VERSION 5.8 ;
BUSBITCHARS "[]" ;
DIVIDERCHAR "/" ;
UNITS
    DATABASE MICRONS 1000 ;
END UNITS

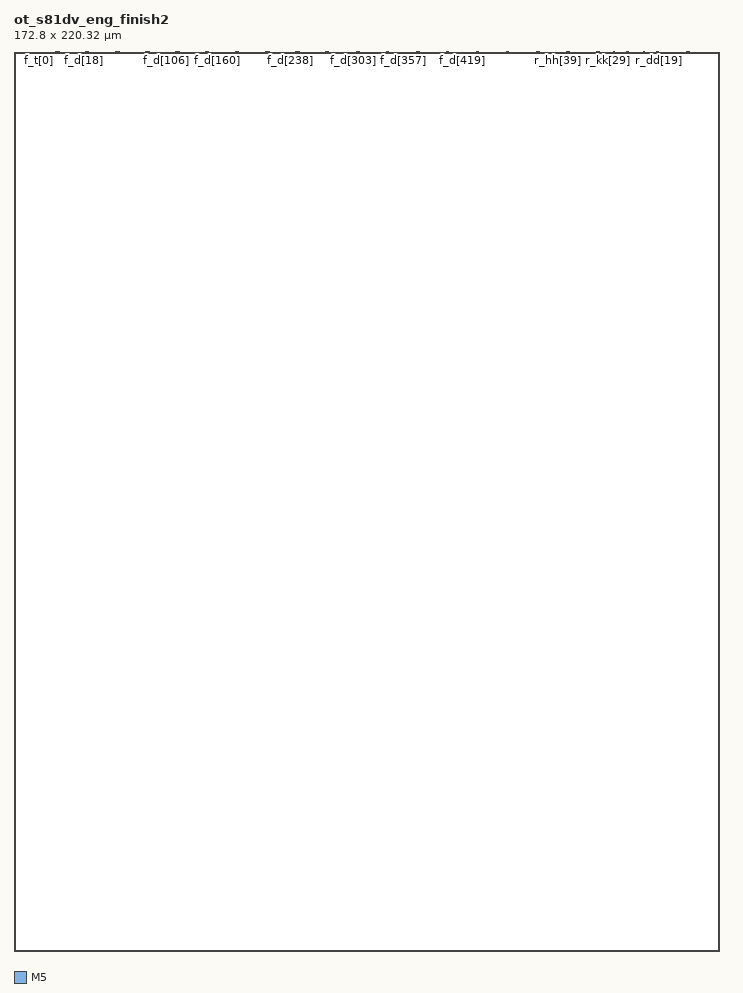
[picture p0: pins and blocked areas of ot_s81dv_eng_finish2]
MACRO ot_s81dv_eng_finish2
  FOREIGN ot_s81dv_eng_finish2 0 0 ;
  CLASS BLOCK ;
  SIZE 172.8 BY 220.32 ;
  PIN go[0]
    DIRECTION INPUT ;
    USE SIGNAL ;
    PORT
      LAYER M5 ;
        RECT 4.3200 220.2360 4.3440 220.3200 ;
    END
  END go[0]
  PIN go[1]
    DIRECTION INPUT ;
    USE SIGNAL ;
    PORT
      LAYER M5 ;
        RECT 4.5600 220.2360 4.5840 220.3200 ;
    END
  END go[1]
  PIN f_v[0]
    DIRECTION INPUT ;
    USE SIGNAL ;
    PORT
      LAYER M5 ;
        RECT 4.8000 220.2360 4.8240 220.3200 ;
    END
  END f_v[0]
  PIN f_v[1]
    DIRECTION INPUT ;
    USE SIGNAL ;
    PORT
      LAYER M5 ;
        RECT 4.9920 220.2360 5.0160 220.3200 ;
    END
  END f_v[1]
  PIN f_v[2]
    DIRECTION INPUT ;
    USE SIGNAL ;
    PORT
      LAYER M5 ;
        RECT 5.2320 220.2360 5.2560 220.3200 ;
    END
  END f_v[2]
  PIN f_v[3]
    DIRECTION INPUT ;
    USE SIGNAL ;
    PORT
      LAYER M5 ;
        RECT 5.4720 220.2360 5.4960 220.3200 ;
    END
  END f_v[3]
  PIN f_v[4]
    DIRECTION INPUT ;
    USE SIGNAL ;
    PORT
      LAYER M5 ;
        RECT 5.7120 220.2360 5.7360 220.3200 ;
    END
  END f_v[4]
  PIN f_v[5]
    DIRECTION INPUT ;
    USE SIGNAL ;
    PORT
      LAYER M5 ;
        RECT 5.9040 220.2360 5.9280 220.3200 ;
    END
  END f_v[5]
  PIN f_t[0]
    DIRECTION INPUT ;
    USE SIGNAL ;
    PORT
      LAYER M5 ;
        RECT 6.1440 220.2360 6.1680 220.3200 ;
    END
  END f_t[0]
  PIN f_t[1]
    DIRECTION INPUT ;
    USE SIGNAL ;
    PORT
      LAYER M5 ;
        RECT 6.3840 220.2360 6.4080 220.3200 ;
    END
  END f_t[1]
  PIN f_t[2]
    DIRECTION INPUT ;
    USE SIGNAL ;
    PORT
      LAYER M5 ;
        RECT 6.6240 220.2360 6.6480 220.3200 ;
    END
  END f_t[2]
  PIN f_t[3]
    DIRECTION INPUT ;
    USE SIGNAL ;
    PORT
      LAYER M5 ;
        RECT 6.8640 220.2360 6.8880 220.3200 ;
    END
  END f_t[3]
  PIN f_t[4]
    DIRECTION INPUT ;
    USE SIGNAL ;
    PORT
      LAYER M5 ;
        RECT 7.0560 220.2360 7.0800 220.3200 ;
    END
  END f_t[4]
  PIN f_t[5]
    DIRECTION INPUT ;
    USE SIGNAL ;
    PORT
      LAYER M5 ;
        RECT 7.2960 220.2360 7.3200 220.3200 ;
    END
  END f_t[5]
  PIN f_base[0]
    DIRECTION INPUT ;
    USE SIGNAL ;
    PORT
      LAYER M5 ;
        RECT 7.5360 220.2360 7.5600 220.3200 ;
    END
  END f_base[0]
  PIN f_base[1]
    DIRECTION INPUT ;
    USE SIGNAL ;
    PORT
      LAYER M5 ;
        RECT 7.7760 220.2360 7.8000 220.3200 ;
    END
  END f_base[1]
  PIN f_base[2]
    DIRECTION INPUT ;
    USE SIGNAL ;
    PORT
      LAYER M5 ;
        RECT 8.0160 220.2360 8.0400 220.3200 ;
    END
  END f_base[2]
  PIN f_base[3]
    DIRECTION INPUT ;
    USE SIGNAL ;
    PORT
      LAYER M5 ;
        RECT 8.2080 220.2360 8.2320 220.3200 ;
    END
  END f_base[3]
  PIN f_base[4]
    DIRECTION INPUT ;
    USE SIGNAL ;
    PORT
      LAYER M5 ;
        RECT 8.4480 220.2360 8.4720 220.3200 ;
    END
  END f_base[4]
  PIN f_base[5]
    DIRECTION INPUT ;
    USE SIGNAL ;
    PORT
      LAYER M5 ;
        RECT 8.6880 220.2360 8.7120 220.3200 ;
    END
  END f_base[5]
  PIN f_base[6]
    DIRECTION INPUT ;
    USE SIGNAL ;
    PORT
      LAYER M5 ;
        RECT 8.9280 220.2360 8.9520 220.3200 ;
    END
  END f_base[6]
  PIN f_base[7]
    DIRECTION INPUT ;
    USE SIGNAL ;
    PORT
      LAYER M5 ;
        RECT 9.1200 220.2360 9.1440 220.3200 ;
    END
  END f_base[7]
  PIN f_base[8]
    DIRECTION INPUT ;
    USE SIGNAL ;
    PORT
      LAYER M5 ;
        RECT 9.3600 220.2360 9.3840 220.3200 ;
    END
  END f_base[8]
  PIN f_base[9]
    DIRECTION INPUT ;
    USE SIGNAL ;
    PORT
      LAYER M5 ;
        RECT 9.6000 220.2360 9.6240 220.3200 ;
    END
  END f_base[9]
  PIN f_base[10]
    DIRECTION INPUT ;
    USE SIGNAL ;
    PORT
      LAYER M5 ;
        RECT 9.8400 220.2360 9.8640 220.3200 ;
    END
  END f_base[10]
  PIN f_base[11]
    DIRECTION INPUT ;
    USE SIGNAL ;
    PORT
      LAYER M5 ;
        RECT 10.0800 220.2360 10.1040 220.3200 ;
    END
  END f_base[11]
  PIN f_base[12]
    DIRECTION INPUT ;
    USE SIGNAL ;
    PORT
      LAYER M5 ;
        RECT 10.2720 220.2360 10.2960 220.3200 ;
    END
  END f_base[12]
  PIN f_base[13]
    DIRECTION INPUT ;
    USE SIGNAL ;
    PORT
      LAYER M5 ;
        RECT 10.5120 220.2360 10.5360 220.3200 ;
    END
  END f_base[13]
  PIN f_base[14]
    DIRECTION INPUT ;
    USE SIGNAL ;
    PORT
      LAYER M5 ;
        RECT 10.7520 220.2360 10.7760 220.3200 ;
    END
  END f_base[14]
  PIN f_base[15]
    DIRECTION INPUT ;
    USE SIGNAL ;
    PORT
      LAYER M5 ;
        RECT 10.9920 220.2360 11.0160 220.3200 ;
    END
  END f_base[15]
  PIN f_base[16]
    DIRECTION INPUT ;
    USE SIGNAL ;
    PORT
      LAYER M5 ;
        RECT 11.1840 220.2360 11.2080 220.3200 ;
    END
  END f_base[16]
  PIN f_base[17]
    DIRECTION INPUT ;
    USE SIGNAL ;
    PORT
      LAYER M5 ;
        RECT 11.4240 220.2360 11.4480 220.3200 ;
    END
  END f_base[17]
  PIN f_base[18]
    DIRECTION INPUT ;
    USE SIGNAL ;
    PORT
      LAYER M5 ;
        RECT 11.6640 220.2360 11.6880 220.3200 ;
    END
  END f_base[18]
  PIN f_base[19]
    DIRECTION INPUT ;
    USE SIGNAL ;
    PORT
      LAYER M5 ;
        RECT 11.9040 220.2360 11.9280 220.3200 ;
    END
  END f_base[19]
  PIN f_base[20]
    DIRECTION INPUT ;
    USE SIGNAL ;
    PORT
      LAYER M5 ;
        RECT 12.1440 220.2360 12.1680 220.3200 ;
    END
  END f_base[20]
  PIN f_base[21]
    DIRECTION INPUT ;
    USE SIGNAL ;
    PORT
      LAYER M5 ;
        RECT 12.3360 220.2360 12.3600 220.3200 ;
    END
  END f_base[21]
  PIN f_base[22]
    DIRECTION INPUT ;
    USE SIGNAL ;
    PORT
      LAYER M5 ;
        RECT 12.5760 220.2360 12.6000 220.3200 ;
    END
  END f_base[22]
  PIN f_base[23]
    DIRECTION INPUT ;
    USE SIGNAL ;
    PORT
      LAYER M5 ;
        RECT 12.8160 220.2360 12.8400 220.3200 ;
    END
  END f_base[23]
  PIN f_d[0]
    DIRECTION INPUT ;
    USE SIGNAL ;
    PORT
      LAYER M5 ;
        RECT 13.0560 220.2360 13.0800 220.3200 ;
    END
  END f_d[0]
  PIN f_d[1]
    DIRECTION INPUT ;
    USE SIGNAL ;
    PORT
      LAYER M5 ;
        RECT 13.2480 220.2360 13.2720 220.3200 ;
    END
  END f_d[1]
  PIN f_d[2]
    DIRECTION INPUT ;
    USE SIGNAL ;
    PORT
      LAYER M5 ;
        RECT 13.4880 220.2360 13.5120 220.3200 ;
    END
  END f_d[2]
  PIN f_d[3]
    DIRECTION INPUT ;
    USE SIGNAL ;
    PORT
      LAYER M5 ;
        RECT 13.7280 220.2360 13.7520 220.3200 ;
    END
  END f_d[3]
  PIN f_d[4]
    DIRECTION INPUT ;
    USE SIGNAL ;
    PORT
      LAYER M5 ;
        RECT 13.9680 220.2360 13.9920 220.3200 ;
    END
  END f_d[4]
  PIN f_d[5]
    DIRECTION INPUT ;
    USE SIGNAL ;
    PORT
      LAYER M5 ;
        RECT 14.2080 220.2360 14.2320 220.3200 ;
    END
  END f_d[5]
  PIN f_d[6]
    DIRECTION INPUT ;
    USE SIGNAL ;
    PORT
      LAYER M5 ;
        RECT 14.4000 220.2360 14.4240 220.3200 ;
    END
  END f_d[6]
  PIN f_d[7]
    DIRECTION INPUT ;
    USE SIGNAL ;
    PORT
      LAYER M5 ;
        RECT 14.6400 220.2360 14.6640 220.3200 ;
    END
  END f_d[7]
  PIN f_d[8]
    DIRECTION INPUT ;
    USE SIGNAL ;
    PORT
      LAYER M5 ;
        RECT 14.8800 220.2360 14.9040 220.3200 ;
    END
  END f_d[8]
  PIN f_d[9]
    DIRECTION INPUT ;
    USE SIGNAL ;
    PORT
      LAYER M5 ;
        RECT 15.1200 220.2360 15.1440 220.3200 ;
    END
  END f_d[9]
  PIN f_d[10]
    DIRECTION INPUT ;
    USE SIGNAL ;
    PORT
      LAYER M5 ;
        RECT 15.3600 220.2360 15.3840 220.3200 ;
    END
  END f_d[10]
  PIN f_d[11]
    DIRECTION INPUT ;
    USE SIGNAL ;
    PORT
      LAYER M5 ;
        RECT 15.5520 220.2360 15.5760 220.3200 ;
    END
  END f_d[11]
  PIN f_d[12]
    DIRECTION INPUT ;
    USE SIGNAL ;
    PORT
      LAYER M5 ;
        RECT 15.7920 220.2360 15.8160 220.3200 ;
    END
  END f_d[12]
  PIN f_d[13]
    DIRECTION INPUT ;
    USE SIGNAL ;
    PORT
      LAYER M5 ;
        RECT 16.0320 220.2360 16.0560 220.3200 ;
    END
  END f_d[13]
  PIN f_d[14]
    DIRECTION INPUT ;
    USE SIGNAL ;
    PORT
      LAYER M5 ;
        RECT 16.2720 220.2360 16.2960 220.3200 ;
    END
  END f_d[14]
  PIN f_d[15]
    DIRECTION INPUT ;
    USE SIGNAL ;
    PORT
      LAYER M5 ;
        RECT 16.4640 220.2360 16.4880 220.3200 ;
    END
  END f_d[15]
  PIN f_d[16]
    DIRECTION INPUT ;
    USE SIGNAL ;
    PORT
      LAYER M5 ;
        RECT 16.7040 220.2360 16.7280 220.3200 ;
    END
  END f_d[16]
  PIN f_d[17]
    DIRECTION INPUT ;
    USE SIGNAL ;
    PORT
      LAYER M5 ;
        RECT 16.9440 220.2360 16.9680 220.3200 ;
    END
  END f_d[17]
  PIN f_d[18]
    DIRECTION INPUT ;
    USE SIGNAL ;
    PORT
      LAYER M5 ;
        RECT 17.1840 220.2360 17.2080 220.3200 ;
    END
  END f_d[18]
  PIN f_d[19]
    DIRECTION INPUT ;
    USE SIGNAL ;
    PORT
      LAYER M5 ;
        RECT 17.4240 220.2360 17.4480 220.3200 ;
    END
  END f_d[19]
  PIN f_d[20]
    DIRECTION INPUT ;
    USE SIGNAL ;
    PORT
      LAYER M5 ;
        RECT 17.6160 220.2360 17.6400 220.3200 ;
    END
  END f_d[20]
  PIN f_d[21]
    DIRECTION INPUT ;
    USE SIGNAL ;
    PORT
      LAYER M5 ;
        RECT 17.8560 220.2360 17.8800 220.3200 ;
    END
  END f_d[21]
  PIN f_d[22]
    DIRECTION INPUT ;
    USE SIGNAL ;
    PORT
      LAYER M5 ;
        RECT 18.0960 220.2360 18.1200 220.3200 ;
    END
  END f_d[22]
  PIN f_d[23]
    DIRECTION INPUT ;
    USE SIGNAL ;
    PORT
      LAYER M5 ;
        RECT 18.3360 220.2360 18.3600 220.3200 ;
    END
  END f_d[23]
  PIN f_d[24]
    DIRECTION INPUT ;
    USE SIGNAL ;
    PORT
      LAYER M5 ;
        RECT 18.5280 220.2360 18.5520 220.3200 ;
    END
  END f_d[24]
  PIN f_d[25]
    DIRECTION INPUT ;
    USE SIGNAL ;
    PORT
      LAYER M5 ;
        RECT 18.7680 220.2360 18.7920 220.3200 ;
    END
  END f_d[25]
  PIN f_d[26]
    DIRECTION INPUT ;
    USE SIGNAL ;
    PORT
      LAYER M5 ;
        RECT 19.0080 220.2360 19.0320 220.3200 ;
    END
  END f_d[26]
  PIN f_d[27]
    DIRECTION INPUT ;
    USE SIGNAL ;
    PORT
      LAYER M5 ;
        RECT 19.2480 220.2360 19.2720 220.3200 ;
    END
  END f_d[27]
  PIN f_d[28]
    DIRECTION INPUT ;
    USE SIGNAL ;
    PORT
      LAYER M5 ;
        RECT 19.4880 220.2360 19.5120 220.3200 ;
    END
  END f_d[28]
  PIN f_d[29]
    DIRECTION INPUT ;
    USE SIGNAL ;
    PORT
      LAYER M5 ;
        RECT 19.6800 220.2360 19.7040 220.3200 ;
    END
  END f_d[29]
  PIN f_d[30]
    DIRECTION INPUT ;
    USE SIGNAL ;
    PORT
      LAYER M5 ;
        RECT 19.9200 220.2360 19.9440 220.3200 ;
    END
  END f_d[30]
  PIN f_d[31]
    DIRECTION INPUT ;
    USE SIGNAL ;
    PORT
      LAYER M5 ;
        RECT 20.1600 220.2360 20.1840 220.3200 ;
    END
  END f_d[31]
  PIN f_d[32]
    DIRECTION INPUT ;
    USE SIGNAL ;
    PORT
      LAYER M5 ;
        RECT 20.4000 220.2360 20.4240 220.3200 ;
    END
  END f_d[32]
  PIN f_d[33]
    DIRECTION INPUT ;
    USE SIGNAL ;
    PORT
      LAYER M5 ;
        RECT 20.6400 220.2360 20.6640 220.3200 ;
    END
  END f_d[33]
  PIN f_d[34]
    DIRECTION INPUT ;
    USE SIGNAL ;
    PORT
      LAYER M5 ;
        RECT 20.8320 220.2360 20.8560 220.3200 ;
    END
  END f_d[34]
  PIN f_d[35]
    DIRECTION INPUT ;
    USE SIGNAL ;
    PORT
      LAYER M5 ;
        RECT 21.0720 220.2360 21.0960 220.3200 ;
    END
  END f_d[35]
  PIN f_d[36]
    DIRECTION INPUT ;
    USE SIGNAL ;
    PORT
      LAYER M5 ;
        RECT 21.3120 220.2360 21.3360 220.3200 ;
    END
  END f_d[36]
  PIN f_d[37]
    DIRECTION INPUT ;
    USE SIGNAL ;
    PORT
      LAYER M5 ;
        RECT 21.5520 220.2360 21.5760 220.3200 ;
    END
  END f_d[37]
  PIN f_d[38]
    DIRECTION INPUT ;
    USE SIGNAL ;
    PORT
      LAYER M5 ;
        RECT 21.7440 220.2360 21.7680 220.3200 ;
    END
  END f_d[38]
  PIN f_d[39]
    DIRECTION INPUT ;
    USE SIGNAL ;
    PORT
      LAYER M5 ;
        RECT 21.9840 220.2360 22.0080 220.3200 ;
    END
  END f_d[39]
  PIN f_d[40]
    DIRECTION INPUT ;
    USE SIGNAL ;
    PORT
      LAYER M5 ;
        RECT 22.2240 220.2360 22.2480 220.3200 ;
    END
  END f_d[40]
  PIN f_d[41]
    DIRECTION INPUT ;
    USE SIGNAL ;
    PORT
      LAYER M5 ;
        RECT 22.4640 220.2360 22.4880 220.3200 ;
    END
  END f_d[41]
  PIN f_d[42]
    DIRECTION INPUT ;
    USE SIGNAL ;
    PORT
      LAYER M5 ;
        RECT 22.7040 220.2360 22.7280 220.3200 ;
    END
  END f_d[42]
  PIN f_d[43]
    DIRECTION INPUT ;
    USE SIGNAL ;
    PORT
      LAYER M5 ;
        RECT 22.8960 220.2360 22.9200 220.3200 ;
    END
  END f_d[43]
  PIN f_d[44]
    DIRECTION INPUT ;
    USE SIGNAL ;
    PORT
      LAYER M5 ;
        RECT 23.1360 220.2360 23.1600 220.3200 ;
    END
  END f_d[44]
  PIN f_d[45]
    DIRECTION INPUT ;
    USE SIGNAL ;
    PORT
      LAYER M5 ;
        RECT 23.3760 220.2360 23.4000 220.3200 ;
    END
  END f_d[45]
  PIN f_d[46]
    DIRECTION INPUT ;
    USE SIGNAL ;
    PORT
      LAYER M5 ;
        RECT 23.6160 220.2360 23.6400 220.3200 ;
    END
  END f_d[46]
  PIN f_d[47]
    DIRECTION INPUT ;
    USE SIGNAL ;
    PORT
      LAYER M5 ;
        RECT 23.8080 220.2360 23.8320 220.3200 ;
    END
  END f_d[47]
  PIN f_d[48]
    DIRECTION INPUT ;
    USE SIGNAL ;
    PORT
      LAYER M5 ;
        RECT 24.0480 220.2360 24.0720 220.3200 ;
    END
  END f_d[48]
  PIN f_d[49]
    DIRECTION INPUT ;
    USE SIGNAL ;
    PORT
      LAYER M5 ;
        RECT 24.2880 220.2360 24.3120 220.3200 ;
    END
  END f_d[49]
  PIN f_d[50]
    DIRECTION INPUT ;
    USE SIGNAL ;
    PORT
      LAYER M5 ;
        RECT 24.5280 220.2360 24.5520 220.3200 ;
    END
  END f_d[50]
  PIN f_d[51]
    DIRECTION INPUT ;
    USE SIGNAL ;
    PORT
      LAYER M5 ;
        RECT 24.7680 220.2360 24.7920 220.3200 ;
    END
  END f_d[51]
  PIN f_d[52]
    DIRECTION INPUT ;
    USE SIGNAL ;
    PORT
      LAYER M5 ;
        RECT 24.9600 220.2360 24.9840 220.3200 ;
    END
  END f_d[52]
  PIN f_d[53]
    DIRECTION INPUT ;
    USE SIGNAL ;
    PORT
      LAYER M5 ;
        RECT 25.2000 220.2360 25.2240 220.3200 ;
    END
  END f_d[53]
  PIN f_d[54]
    DIRECTION INPUT ;
    USE SIGNAL ;
    PORT
      LAYER M5 ;
        RECT 25.4400 220.2360 25.4640 220.3200 ;
    END
  END f_d[54]
  PIN f_d[55]
    DIRECTION INPUT ;
    USE SIGNAL ;
    PORT
      LAYER M5 ;
        RECT 25.6800 220.2360 25.7040 220.3200 ;
    END
  END f_d[55]
  PIN f_d[56]
    DIRECTION INPUT ;
    USE SIGNAL ;
    PORT
      LAYER M5 ;
        RECT 25.8720 220.2360 25.8960 220.3200 ;
    END
  END f_d[56]
  PIN f_d[57]
    DIRECTION INPUT ;
    USE SIGNAL ;
    PORT
      LAYER M5 ;
        RECT 26.1120 220.2360 26.1360 220.3200 ;
    END
  END f_d[57]
  PIN f_d[58]
    DIRECTION INPUT ;
    USE SIGNAL ;
    PORT
      LAYER M5 ;
        RECT 26.3520 220.2360 26.3760 220.3200 ;
    END
  END f_d[58]
  PIN f_d[59]
    DIRECTION INPUT ;
    USE SIGNAL ;
    PORT
      LAYER M5 ;
        RECT 26.5920 220.2360 26.6160 220.3200 ;
    END
  END f_d[59]
  PIN f_d[60]
    DIRECTION INPUT ;
    USE SIGNAL ;
    PORT
      LAYER M5 ;
        RECT 26.8320 220.2360 26.8560 220.3200 ;
    END
  END f_d[60]
  PIN f_d[61]
    DIRECTION INPUT ;
    USE SIGNAL ;
    PORT
      LAYER M5 ;
        RECT 27.0240 220.2360 27.0480 220.3200 ;
    END
  END f_d[61]
  PIN f_d[62]
    DIRECTION INPUT ;
    USE SIGNAL ;
    PORT
      LAYER M5 ;
        RECT 27.2640 220.2360 27.2880 220.3200 ;
    END
  END f_d[62]
  PIN f_d[63]
    DIRECTION INPUT ;
    USE SIGNAL ;
    PORT
      LAYER M5 ;
        RECT 27.5040 220.2360 27.5280 220.3200 ;
    END
  END f_d[63]
  PIN f_d[64]
    DIRECTION INPUT ;
    USE SIGNAL ;
    PORT
      LAYER M5 ;
        RECT 27.7440 220.2360 27.7680 220.3200 ;
    END
  END f_d[64]
  PIN f_d[65]
    DIRECTION INPUT ;
    USE SIGNAL ;
    PORT
      LAYER M5 ;
        RECT 27.9840 220.2360 28.0080 220.3200 ;
    END
  END f_d[65]
  PIN f_d[66]
    DIRECTION INPUT ;
    USE SIGNAL ;
    PORT
      LAYER M5 ;
        RECT 28.1760 220.2360 28.2000 220.3200 ;
    END
  END f_d[66]
  PIN f_d[67]
    DIRECTION INPUT ;
    USE SIGNAL ;
    PORT
      LAYER M5 ;
        RECT 28.4160 220.2360 28.4400 220.3200 ;
    END
  END f_d[67]
  PIN f_d[68]
    DIRECTION INPUT ;
    USE SIGNAL ;
    PORT
      LAYER M5 ;
        RECT 28.6560 220.2360 28.6800 220.3200 ;
    END
  END f_d[68]
  PIN f_d[69]
    DIRECTION INPUT ;
    USE SIGNAL ;
    PORT
      LAYER M5 ;
        RECT 28.8960 220.2360 28.9200 220.3200 ;
    END
  END f_d[69]
  PIN f_d[70]
    DIRECTION INPUT ;
    USE SIGNAL ;
    PORT
      LAYER M5 ;
        RECT 29.0880 220.2360 29.1120 220.3200 ;
    END
  END f_d[70]
  PIN f_d[71]
    DIRECTION INPUT ;
    USE SIGNAL ;
    PORT
      LAYER M5 ;
        RECT 29.3280 220.2360 29.3520 220.3200 ;
    END
  END f_d[71]
  PIN f_d[72]
    DIRECTION INPUT ;
    USE SIGNAL ;
    PORT
      LAYER M5 ;
        RECT 29.5680 220.2360 29.5920 220.3200 ;
    END
  END f_d[72]
  PIN f_d[73]
    DIRECTION INPUT ;
    USE SIGNAL ;
    PORT
      LAYER M5 ;
        RECT 29.8080 220.2360 29.8320 220.3200 ;
    END
  END f_d[73]
  PIN f_d[74]
    DIRECTION INPUT ;
    USE SIGNAL ;
    PORT
      LAYER M5 ;
        RECT 30.0480 220.2360 30.0720 220.3200 ;
    END
  END f_d[74]
  PIN f_d[75]
    DIRECTION INPUT ;
    USE SIGNAL ;
    PORT
      LAYER M5 ;
        RECT 30.2400 220.2360 30.2640 220.3200 ;
    END
  END f_d[75]
  PIN f_d[76]
    DIRECTION INPUT ;
    USE SIGNAL ;
    PORT
      LAYER M5 ;
        RECT 30.4800 220.2360 30.5040 220.3200 ;
    END
  END f_d[76]
  PIN f_d[77]
    DIRECTION INPUT ;
    USE SIGNAL ;
    PORT
      LAYER M5 ;
        RECT 30.7200 220.2360 30.7440 220.3200 ;
    END
  END f_d[77]
  PIN f_d[78]
    DIRECTION INPUT ;
    USE SIGNAL ;
    PORT
      LAYER M5 ;
        RECT 30.9600 220.2360 30.9840 220.3200 ;
    END
  END f_d[78]
  PIN f_d[79]
    DIRECTION INPUT ;
    USE SIGNAL ;
    PORT
      LAYER M5 ;
        RECT 31.1520 220.2360 31.1760 220.3200 ;
    END
  END f_d[79]
  PIN f_d[80]
    DIRECTION INPUT ;
    USE SIGNAL ;
    PORT
      LAYER M5 ;
        RECT 31.3920 220.2360 31.4160 220.3200 ;
    END
  END f_d[80]
  PIN f_d[81]
    DIRECTION INPUT ;
    USE SIGNAL ;
    PORT
      LAYER M5 ;
        RECT 31.6320 220.2360 31.6560 220.3200 ;
    END
  END f_d[81]
  PIN f_d[82]
    DIRECTION INPUT ;
    USE SIGNAL ;
    PORT
      LAYER M5 ;
        RECT 31.8720 220.2360 31.8960 220.3200 ;
    END
  END f_d[82]
  PIN f_d[83]
    DIRECTION INPUT ;
    USE SIGNAL ;
    PORT
      LAYER M5 ;
        RECT 32.1120 220.2360 32.1360 220.3200 ;
    END
  END f_d[83]
  PIN f_d[84]
    DIRECTION INPUT ;
    USE SIGNAL ;
    PORT
      LAYER M5 ;
        RECT 32.3040 220.2360 32.3280 220.3200 ;
    END
  END f_d[84]
  PIN f_d[85]
    DIRECTION INPUT ;
    USE SIGNAL ;
    PORT
      LAYER M5 ;
        RECT 32.5440 220.2360 32.5680 220.3200 ;
    END
  END f_d[85]
  PIN f_d[86]
    DIRECTION INPUT ;
    USE SIGNAL ;
    PORT
      LAYER M5 ;
        RECT 32.7840 220.2360 32.8080 220.3200 ;
    END
  END f_d[86]
  PIN f_d[87]
    DIRECTION INPUT ;
    USE SIGNAL ;
    PORT
      LAYER M5 ;
        RECT 33.0240 220.2360 33.0480 220.3200 ;
    END
  END f_d[87]
  PIN f_d[88]
    DIRECTION INPUT ;
    USE SIGNAL ;
    PORT
      LAYER M5 ;
        RECT 33.2640 220.2360 33.2880 220.3200 ;
    END
  END f_d[88]
  PIN f_d[89]
    DIRECTION INPUT ;
    USE SIGNAL ;
    PORT
      LAYER M5 ;
        RECT 33.4560 220.2360 33.4800 220.3200 ;
    END
  END f_d[89]
  PIN f_d[90]
    DIRECTION INPUT ;
    USE SIGNAL ;
    PORT
      LAYER M5 ;
        RECT 33.6960 220.2360 33.7200 220.3200 ;
    END
  END f_d[90]
  PIN f_d[91]
    DIRECTION INPUT ;
    USE SIGNAL ;
    PORT
      LAYER M5 ;
        RECT 33.9360 220.2360 33.9600 220.3200 ;
    END
  END f_d[91]
  PIN f_d[92]
    DIRECTION INPUT ;
    USE SIGNAL ;
    PORT
      LAYER M5 ;
        RECT 34.1760 220.2360 34.2000 220.3200 ;
    END
  END f_d[92]
  PIN f_d[93]
    DIRECTION INPUT ;
    USE SIGNAL ;
    PORT
      LAYER M5 ;
        RECT 34.3680 220.2360 34.3920 220.3200 ;
    END
  END f_d[93]
  PIN f_d[94]
    DIRECTION INPUT ;
    USE SIGNAL ;
    PORT
      LAYER M5 ;
        RECT 34.6080 220.2360 34.6320 220.3200 ;
    END
  END f_d[94]
  PIN f_d[95]
    DIRECTION INPUT ;
    USE SIGNAL ;
    PORT
      LAYER M5 ;
        RECT 34.8480 220.2360 34.8720 220.3200 ;
    END
  END f_d[95]
  PIN f_d[96]
    DIRECTION INPUT ;
    USE SIGNAL ;
    PORT
      LAYER M5 ;
        RECT 35.0880 220.2360 35.1120 220.3200 ;
    END
  END f_d[96]
  PIN f_d[97]
    DIRECTION INPUT ;
    USE SIGNAL ;
    PORT
      LAYER M5 ;
        RECT 35.3280 220.2360 35.3520 220.3200 ;
    END
  END f_d[97]
  PIN f_d[98]
    DIRECTION INPUT ;
    USE SIGNAL ;
    PORT
      LAYER M5 ;
        RECT 35.5200 220.2360 35.5440 220.3200 ;
    END
  END f_d[98]
  PIN f_d[99]
    DIRECTION INPUT ;
    USE SIGNAL ;
    PORT
      LAYER M5 ;
        RECT 35.7600 220.2360 35.7840 220.3200 ;
    END
  END f_d[99]
  PIN f_d[100]
    DIRECTION INPUT ;
    USE SIGNAL ;
    PORT
      LAYER M5 ;
        RECT 36.0000 220.2360 36.0240 220.3200 ;
    END
  END f_d[100]
  PIN f_d[101]
    DIRECTION INPUT ;
    USE SIGNAL ;
    PORT
      LAYER M5 ;
        RECT 36.2400 220.2360 36.2640 220.3200 ;
    END
  END f_d[101]
  PIN f_d[102]
    DIRECTION INPUT ;
    USE SIGNAL ;
    PORT
      LAYER M5 ;
        RECT 36.4320 220.2360 36.4560 220.3200 ;
    END
  END f_d[102]
  PIN f_d[103]
    DIRECTION INPUT ;
    USE SIGNAL ;
    PORT
      LAYER M5 ;
        RECT 36.6720 220.2360 36.6960 220.3200 ;
    END
  END f_d[103]
  PIN f_d[104]
    DIRECTION INPUT ;
    USE SIGNAL ;
    PORT
      LAYER M5 ;
        RECT 36.9120 220.2360 36.9360 220.3200 ;
    END
  END f_d[104]
  PIN f_d[105]
    DIRECTION INPUT ;
    USE SIGNAL ;
    PORT
      LAYER M5 ;
        RECT 37.1520 220.2360 37.1760 220.3200 ;
    END
  END f_d[105]
  PIN f_d[106]
    DIRECTION INPUT ;
    USE SIGNAL ;
    PORT
      LAYER M5 ;
        RECT 37.3920 220.2360 37.4160 220.3200 ;
    END
  END f_d[106]
  PIN f_d[107]
    DIRECTION INPUT ;
    USE SIGNAL ;
    PORT
      LAYER M5 ;
        RECT 37.5840 220.2360 37.6080 220.3200 ;
    END
  END f_d[107]
  PIN f_d[108]
    DIRECTION INPUT ;
    USE SIGNAL ;
    PORT
      LAYER M5 ;
        RECT 37.8240 220.2360 37.8480 220.3200 ;
    END
  END f_d[108]
  PIN f_d[109]
    DIRECTION INPUT ;
    USE SIGNAL ;
    PORT
      LAYER M5 ;
        RECT 38.0640 220.2360 38.0880 220.3200 ;
    END
  END f_d[109]
  PIN f_d[110]
    DIRECTION INPUT ;
    USE SIGNAL ;
    PORT
      LAYER M5 ;
        RECT 38.3040 220.2360 38.3280 220.3200 ;
    END
  END f_d[110]
  PIN f_d[111]
    DIRECTION INPUT ;
    USE SIGNAL ;
    PORT
      LAYER M5 ;
        RECT 38.4960 220.2360 38.5200 220.3200 ;
    END
  END f_d[111]
  PIN f_d[112]
    DIRECTION INPUT ;
    USE SIGNAL ;
    PORT
      LAYER M5 ;
        RECT 38.7360 220.2360 38.7600 220.3200 ;
    END
  END f_d[112]
  PIN f_d[113]
    DIRECTION INPUT ;
    USE SIGNAL ;
    PORT
      LAYER M5 ;
        RECT 38.9760 220.2360 39.0000 220.3200 ;
    END
  END f_d[113]
  PIN f_d[114]
    DIRECTION INPUT ;
    USE SIGNAL ;
    PORT
      LAYER M5 ;
        RECT 39.2160 220.2360 39.2400 220.3200 ;
    END
  END f_d[114]
  PIN f_d[115]
    DIRECTION INPUT ;
    USE SIGNAL ;
    PORT
      LAYER M5 ;
        RECT 39.4560 220.2360 39.4800 220.3200 ;
    END
  END f_d[115]
  PIN f_d[116]
    DIRECTION INPUT ;
    USE SIGNAL ;
    PORT
      LAYER M5 ;
        RECT 39.6480 220.2360 39.6720 220.3200 ;
    END
  END f_d[116]
  PIN f_d[117]
    DIRECTION INPUT ;
    USE SIGNAL ;
    PORT
      LAYER M5 ;
        RECT 39.8880 220.2360 39.9120 220.3200 ;
    END
  END f_d[117]
  PIN f_d[118]
    DIRECTION INPUT ;
    USE SIGNAL ;
    PORT
      LAYER M5 ;
        RECT 40.1280 220.2360 40.1520 220.3200 ;
    END
  END f_d[118]
  PIN f_d[119]
    DIRECTION INPUT ;
    USE SIGNAL ;
    PORT
      LAYER M5 ;
        RECT 40.3680 220.2360 40.3920 220.3200 ;
    END
  END f_d[119]
  PIN f_d[120]
    DIRECTION INPUT ;
    USE SIGNAL ;
    PORT
      LAYER M5 ;
        RECT 40.6080 220.2360 40.6320 220.3200 ;
    END
  END f_d[120]
  PIN f_d[121]
    DIRECTION INPUT ;
    USE SIGNAL ;
    PORT
      LAYER M5 ;
        RECT 40.8000 220.2360 40.8240 220.3200 ;
    END
  END f_d[121]
  PIN f_d[122]
    DIRECTION INPUT ;
    USE SIGNAL ;
    PORT
      LAYER M5 ;
        RECT 41.0400 220.2360 41.0640 220.3200 ;
    END
  END f_d[122]
  PIN f_d[123]
    DIRECTION INPUT ;
    USE SIGNAL ;
    PORT
      LAYER M5 ;
        RECT 41.2800 220.2360 41.3040 220.3200 ;
    END
  END f_d[123]
  PIN f_d[124]
    DIRECTION INPUT ;
    USE SIGNAL ;
    PORT
      LAYER M5 ;
        RECT 41.5200 220.2360 41.5440 220.3200 ;
    END
  END f_d[124]
  PIN f_d[125]
    DIRECTION INPUT ;
    USE SIGNAL ;
    PORT
      LAYER M5 ;
        RECT 41.7120 220.2360 41.7360 220.3200 ;
    END
  END f_d[125]
  PIN f_d[126]
    DIRECTION INPUT ;
    USE SIGNAL ;
    PORT
      LAYER M5 ;
        RECT 41.9520 220.2360 41.9760 220.3200 ;
    END
  END f_d[126]
  PIN f_d[127]
    DIRECTION INPUT ;
    USE SIGNAL ;
    PORT
      LAYER M5 ;
        RECT 42.1920 220.2360 42.2160 220.3200 ;
    END
  END f_d[127]
  PIN f_d[128]
    DIRECTION INPUT ;
    USE SIGNAL ;
    PORT
      LAYER M5 ;
        RECT 42.4320 220.2360 42.4560 220.3200 ;
    END
  END f_d[128]
  PIN f_d[129]
    DIRECTION INPUT ;
    USE SIGNAL ;
    PORT
      LAYER M5 ;
        RECT 42.6720 220.2360 42.6960 220.3200 ;
    END
  END f_d[129]
  PIN f_d[130]
    DIRECTION INPUT ;
    USE SIGNAL ;
    PORT
      LAYER M5 ;
        RECT 42.8640 220.2360 42.8880 220.3200 ;
    END
  END f_d[130]
  PIN f_d[131]
    DIRECTION INPUT ;
    USE SIGNAL ;
    PORT
      LAYER M5 ;
        RECT 43.1040 220.2360 43.1280 220.3200 ;
    END
  END f_d[131]
  PIN f_d[132]
    DIRECTION INPUT ;
    USE SIGNAL ;
    PORT
      LAYER M5 ;
        RECT 43.3440 220.2360 43.3680 220.3200 ;
    END
  END f_d[132]
  PIN f_d[133]
    DIRECTION INPUT ;
    USE SIGNAL ;
    PORT
      LAYER M5 ;
        RECT 43.5840 220.2360 43.6080 220.3200 ;
    END
  END f_d[133]
  PIN f_d[134]
    DIRECTION INPUT ;
    USE SIGNAL ;
    PORT
      LAYER M5 ;
        RECT 43.7760 220.2360 43.8000 220.3200 ;
    END
  END f_d[134]
  PIN f_d[135]
    DIRECTION INPUT ;
    USE SIGNAL ;
    PORT
      LAYER M5 ;
        RECT 44.0160 220.2360 44.0400 220.3200 ;
    END
  END f_d[135]
  PIN f_d[136]
    DIRECTION INPUT ;
    USE SIGNAL ;
    PORT
      LAYER M5 ;
        RECT 44.2560 220.2360 44.2800 220.3200 ;
    END
  END f_d[136]
  PIN f_d[137]
    DIRECTION INPUT ;
    USE SIGNAL ;
    PORT
      LAYER M5 ;
        RECT 44.4960 220.2360 44.5200 220.3200 ;
    END
  END f_d[137]
  PIN f_d[138]
    DIRECTION INPUT ;
    USE SIGNAL ;
    PORT
      LAYER M5 ;
        RECT 44.7360 220.2360 44.7600 220.3200 ;
    END
  END f_d[138]
  PIN f_d[139]
    DIRECTION INPUT ;
    USE SIGNAL ;
    PORT
      LAYER M5 ;
        RECT 44.9280 220.2360 44.9520 220.3200 ;
    END
  END f_d[139]
  PIN f_d[140]
    DIRECTION INPUT ;
    USE SIGNAL ;
    PORT
      LAYER M5 ;
        RECT 45.1680 220.2360 45.1920 220.3200 ;
    END
  END f_d[140]
  PIN f_d[141]
    DIRECTION INPUT ;
    USE SIGNAL ;
    PORT
      LAYER M5 ;
        RECT 45.4080 220.2360 45.4320 220.3200 ;
    END
  END f_d[141]
  PIN f_d[142]
    DIRECTION INPUT ;
    USE SIGNAL ;
    PORT
      LAYER M5 ;
        RECT 45.6480 220.2360 45.6720 220.3200 ;
    END
  END f_d[142]
  PIN f_d[143]
    DIRECTION INPUT ;
    USE SIGNAL ;
    PORT
      LAYER M5 ;
        RECT 45.8880 220.2360 45.9120 220.3200 ;
    END
  END f_d[143]
  PIN f_d[144]
    DIRECTION INPUT ;
    USE SIGNAL ;
    PORT
      LAYER M5 ;
        RECT 46.0800 220.2360 46.1040 220.3200 ;
    END
  END f_d[144]
  PIN f_d[145]
    DIRECTION INPUT ;
    USE SIGNAL ;
    PORT
      LAYER M5 ;
        RECT 46.3200 220.2360 46.3440 220.3200 ;
    END
  END f_d[145]
  PIN f_d[146]
    DIRECTION INPUT ;
    USE SIGNAL ;
    PORT
      LAYER M5 ;
        RECT 46.5600 220.2360 46.5840 220.3200 ;
    END
  END f_d[146]
  PIN f_d[147]
    DIRECTION INPUT ;
    USE SIGNAL ;
    PORT
      LAYER M5 ;
        RECT 46.8000 220.2360 46.8240 220.3200 ;
    END
  END f_d[147]
  PIN f_d[148]
    DIRECTION INPUT ;
    USE SIGNAL ;
    PORT
      LAYER M5 ;
        RECT 46.9920 220.2360 47.0160 220.3200 ;
    END
  END f_d[148]
  PIN f_d[149]
    DIRECTION INPUT ;
    USE SIGNAL ;
    PORT
      LAYER M5 ;
        RECT 47.2320 220.2360 47.2560 220.3200 ;
    END
  END f_d[149]
  PIN f_d[150]
    DIRECTION INPUT ;
    USE SIGNAL ;
    PORT
      LAYER M5 ;
        RECT 47.4720 220.2360 47.4960 220.3200 ;
    END
  END f_d[150]
  PIN f_d[151]
    DIRECTION INPUT ;
    USE SIGNAL ;
    PORT
      LAYER M5 ;
        RECT 47.7120 220.2360 47.7360 220.3200 ;
    END
  END f_d[151]
  PIN f_d[152]
    DIRECTION INPUT ;
    USE SIGNAL ;
    PORT
      LAYER M5 ;
        RECT 47.9520 220.2360 47.9760 220.3200 ;
    END
  END f_d[152]
  PIN f_d[153]
    DIRECTION INPUT ;
    USE SIGNAL ;
    PORT
      LAYER M5 ;
        RECT 48.1440 220.2360 48.1680 220.3200 ;
    END
  END f_d[153]
  PIN f_d[154]
    DIRECTION INPUT ;
    USE SIGNAL ;
    PORT
      LAYER M5 ;
        RECT 48.3840 220.2360 48.4080 220.3200 ;
    END
  END f_d[154]
  PIN f_d[155]
    DIRECTION INPUT ;
    USE SIGNAL ;
    PORT
      LAYER M5 ;
        RECT 48.6240 220.2360 48.6480 220.3200 ;
    END
  END f_d[155]
  PIN f_d[156]
    DIRECTION INPUT ;
    USE SIGNAL ;
    PORT
      LAYER M5 ;
        RECT 48.8640 220.2360 48.8880 220.3200 ;
    END
  END f_d[156]
  PIN f_d[157]
    DIRECTION INPUT ;
    USE SIGNAL ;
    PORT
      LAYER M5 ;
        RECT 49.0560 220.2360 49.0800 220.3200 ;
    END
  END f_d[157]
  PIN f_d[158]
    DIRECTION INPUT ;
    USE SIGNAL ;
    PORT
      LAYER M5 ;
        RECT 49.2960 220.2360 49.3200 220.3200 ;
    END
  END f_d[158]
  PIN f_d[159]
    DIRECTION INPUT ;
    USE SIGNAL ;
    PORT
      LAYER M5 ;
        RECT 49.5360 220.2360 49.5600 220.3200 ;
    END
  END f_d[159]
  PIN f_d[160]
    DIRECTION INPUT ;
    USE SIGNAL ;
    PORT
      LAYER M5 ;
        RECT 49.7760 220.2360 49.8000 220.3200 ;
    END
  END f_d[160]
  PIN f_d[161]
    DIRECTION INPUT ;
    USE SIGNAL ;
    PORT
      LAYER M5 ;
        RECT 50.0160 220.2360 50.0400 220.3200 ;
    END
  END f_d[161]
  PIN f_d[162]
    DIRECTION INPUT ;
    USE SIGNAL ;
    PORT
      LAYER M5 ;
        RECT 50.2080 220.2360 50.2320 220.3200 ;
    END
  END f_d[162]
  PIN f_d[163]
    DIRECTION INPUT ;
    USE SIGNAL ;
    PORT
      LAYER M5 ;
        RECT 50.4480 220.2360 50.4720 220.3200 ;
    END
  END f_d[163]
  PIN f_d[164]
    DIRECTION INPUT ;
    USE SIGNAL ;
    PORT
      LAYER M5 ;
        RECT 50.6880 220.2360 50.7120 220.3200 ;
    END
  END f_d[164]
  PIN f_d[165]
    DIRECTION INPUT ;
    USE SIGNAL ;
    PORT
      LAYER M5 ;
        RECT 50.9280 220.2360 50.9520 220.3200 ;
    END
  END f_d[165]
  PIN f_d[166]
    DIRECTION INPUT ;
    USE SIGNAL ;
    PORT
      LAYER M5 ;
        RECT 51.1200 220.2360 51.1440 220.3200 ;
    END
  END f_d[166]
  PIN f_d[167]
    DIRECTION INPUT ;
    USE SIGNAL ;
    PORT
      LAYER M5 ;
        RECT 51.3600 220.2360 51.3840 220.3200 ;
    END
  END f_d[167]
  PIN f_d[168]
    DIRECTION INPUT ;
    USE SIGNAL ;
    PORT
      LAYER M5 ;
        RECT 51.6000 220.2360 51.6240 220.3200 ;
    END
  END f_d[168]
  PIN f_d[169]
    DIRECTION INPUT ;
    USE SIGNAL ;
    PORT
      LAYER M5 ;
        RECT 51.8400 220.2360 51.8640 220.3200 ;
    END
  END f_d[169]
  PIN f_d[170]
    DIRECTION INPUT ;
    USE SIGNAL ;
    PORT
      LAYER M5 ;
        RECT 52.0800 220.2360 52.1040 220.3200 ;
    END
  END f_d[170]
  PIN f_d[171]
    DIRECTION INPUT ;
    USE SIGNAL ;
    PORT
      LAYER M5 ;
        RECT 52.2720 220.2360 52.2960 220.3200 ;
    END
  END f_d[171]
  PIN f_d[172]
    DIRECTION INPUT ;
    USE SIGNAL ;
    PORT
      LAYER M5 ;
        RECT 52.5120 220.2360 52.5360 220.3200 ;
    END
  END f_d[172]
  PIN f_d[173]
    DIRECTION INPUT ;
    USE SIGNAL ;
    PORT
      LAYER M5 ;
        RECT 52.7520 220.2360 52.7760 220.3200 ;
    END
  END f_d[173]
  PIN f_d[174]
    DIRECTION INPUT ;
    USE SIGNAL ;
    PORT
      LAYER M5 ;
        RECT 52.9920 220.2360 53.0160 220.3200 ;
    END
  END f_d[174]
  PIN f_d[175]
    DIRECTION INPUT ;
    USE SIGNAL ;
    PORT
      LAYER M5 ;
        RECT 53.2320 220.2360 53.2560 220.3200 ;
    END
  END f_d[175]
  PIN f_d[176]
    DIRECTION INPUT ;
    USE SIGNAL ;
    PORT
      LAYER M5 ;
        RECT 53.4240 220.2360 53.4480 220.3200 ;
    END
  END f_d[176]
  PIN f_d[177]
    DIRECTION INPUT ;
    USE SIGNAL ;
    PORT
      LAYER M5 ;
        RECT 53.6640 220.2360 53.6880 220.3200 ;
    END
  END f_d[177]
  PIN f_d[178]
    DIRECTION INPUT ;
    USE SIGNAL ;
    PORT
      LAYER M5 ;
        RECT 53.9040 220.2360 53.9280 220.3200 ;
    END
  END f_d[178]
  PIN f_d[179]
    DIRECTION INPUT ;
    USE SIGNAL ;
    PORT
      LAYER M5 ;
        RECT 54.1440 220.2360 54.1680 220.3200 ;
    END
  END f_d[179]
  PIN f_d[180]
    DIRECTION INPUT ;
    USE SIGNAL ;
    PORT
      LAYER M5 ;
        RECT 54.3360 220.2360 54.3600 220.3200 ;
    END
  END f_d[180]
  PIN f_d[181]
    DIRECTION INPUT ;
    USE SIGNAL ;
    PORT
      LAYER M5 ;
        RECT 54.5760 220.2360 54.6000 220.3200 ;
    END
  END f_d[181]
  PIN f_d[182]
    DIRECTION INPUT ;
    USE SIGNAL ;
    PORT
      LAYER M5 ;
        RECT 54.8160 220.2360 54.8400 220.3200 ;
    END
  END f_d[182]
  PIN f_d[183]
    DIRECTION INPUT ;
    USE SIGNAL ;
    PORT
      LAYER M5 ;
        RECT 55.0560 220.2360 55.0800 220.3200 ;
    END
  END f_d[183]
  PIN f_d[184]
    DIRECTION INPUT ;
    USE SIGNAL ;
    PORT
      LAYER M5 ;
        RECT 55.2960 220.2360 55.3200 220.3200 ;
    END
  END f_d[184]
  PIN f_d[185]
    DIRECTION INPUT ;
    USE SIGNAL ;
    PORT
      LAYER M5 ;
        RECT 55.4880 220.2360 55.5120 220.3200 ;
    END
  END f_d[185]
  PIN f_d[186]
    DIRECTION INPUT ;
    USE SIGNAL ;
    PORT
      LAYER M5 ;
        RECT 55.7280 220.2360 55.7520 220.3200 ;
    END
  END f_d[186]
  PIN f_d[187]
    DIRECTION INPUT ;
    USE SIGNAL ;
    PORT
      LAYER M5 ;
        RECT 55.9680 220.2360 55.9920 220.3200 ;
    END
  END f_d[187]
  PIN f_d[188]
    DIRECTION INPUT ;
    USE SIGNAL ;
    PORT
      LAYER M5 ;
        RECT 56.2080 220.2360 56.2320 220.3200 ;
    END
  END f_d[188]
  PIN f_d[189]
    DIRECTION INPUT ;
    USE SIGNAL ;
    PORT
      LAYER M5 ;
        RECT 56.4000 220.2360 56.4240 220.3200 ;
    END
  END f_d[189]
  PIN f_d[190]
    DIRECTION INPUT ;
    USE SIGNAL ;
    PORT
      LAYER M5 ;
        RECT 56.6400 220.2360 56.6640 220.3200 ;
    END
  END f_d[190]
  PIN f_d[191]
    DIRECTION INPUT ;
    USE SIGNAL ;
    PORT
      LAYER M5 ;
        RECT 56.8800 220.2360 56.9040 220.3200 ;
    END
  END f_d[191]
  PIN f_d[192]
    DIRECTION INPUT ;
    USE SIGNAL ;
    PORT
      LAYER M5 ;
        RECT 57.1200 220.2360 57.1440 220.3200 ;
    END
  END f_d[192]
  PIN f_d[193]
    DIRECTION INPUT ;
    USE SIGNAL ;
    PORT
      LAYER M5 ;
        RECT 57.3600 220.2360 57.3840 220.3200 ;
    END
  END f_d[193]
  PIN f_d[194]
    DIRECTION INPUT ;
    USE SIGNAL ;
    PORT
      LAYER M5 ;
        RECT 57.5520 220.2360 57.5760 220.3200 ;
    END
  END f_d[194]
  PIN f_d[195]
    DIRECTION INPUT ;
    USE SIGNAL ;
    PORT
      LAYER M5 ;
        RECT 57.7920 220.2360 57.8160 220.3200 ;
    END
  END f_d[195]
  PIN f_d[196]
    DIRECTION INPUT ;
    USE SIGNAL ;
    PORT
      LAYER M5 ;
        RECT 58.0320 220.2360 58.0560 220.3200 ;
    END
  END f_d[196]
  PIN f_d[197]
    DIRECTION INPUT ;
    USE SIGNAL ;
    PORT
      LAYER M5 ;
        RECT 58.2720 220.2360 58.2960 220.3200 ;
    END
  END f_d[197]
  PIN f_d[198]
    DIRECTION INPUT ;
    USE SIGNAL ;
    PORT
      LAYER M5 ;
        RECT 58.5120 220.2360 58.5360 220.3200 ;
    END
  END f_d[198]
  PIN f_d[199]
    DIRECTION INPUT ;
    USE SIGNAL ;
    PORT
      LAYER M5 ;
        RECT 58.7040 220.2360 58.7280 220.3200 ;
    END
  END f_d[199]
  PIN f_d[200]
    DIRECTION INPUT ;
    USE SIGNAL ;
    PORT
      LAYER M5 ;
        RECT 58.9440 220.2360 58.9680 220.3200 ;
    END
  END f_d[200]
  PIN f_d[201]
    DIRECTION INPUT ;
    USE SIGNAL ;
    PORT
      LAYER M5 ;
        RECT 59.1840 220.2360 59.2080 220.3200 ;
    END
  END f_d[201]
  PIN f_d[202]
    DIRECTION INPUT ;
    USE SIGNAL ;
    PORT
      LAYER M5 ;
        RECT 59.4240 220.2360 59.4480 220.3200 ;
    END
  END f_d[202]
  PIN f_d[203]
    DIRECTION INPUT ;
    USE SIGNAL ;
    PORT
      LAYER M5 ;
        RECT 59.6160 220.2360 59.6400 220.3200 ;
    END
  END f_d[203]
  PIN f_d[204]
    DIRECTION INPUT ;
    USE SIGNAL ;
    PORT
      LAYER M5 ;
        RECT 59.8560 220.2360 59.8800 220.3200 ;
    END
  END f_d[204]
  PIN f_d[205]
    DIRECTION INPUT ;
    USE SIGNAL ;
    PORT
      LAYER M5 ;
        RECT 60.0960 220.2360 60.1200 220.3200 ;
    END
  END f_d[205]
  PIN f_d[206]
    DIRECTION INPUT ;
    USE SIGNAL ;
    PORT
      LAYER M5 ;
        RECT 60.3360 220.2360 60.3600 220.3200 ;
    END
  END f_d[206]
  PIN f_d[207]
    DIRECTION INPUT ;
    USE SIGNAL ;
    PORT
      LAYER M5 ;
        RECT 60.5760 220.2360 60.6000 220.3200 ;
    END
  END f_d[207]
  PIN f_d[208]
    DIRECTION INPUT ;
    USE SIGNAL ;
    PORT
      LAYER M5 ;
        RECT 60.7680 220.2360 60.7920 220.3200 ;
    END
  END f_d[208]
  PIN f_d[209]
    DIRECTION INPUT ;
    USE SIGNAL ;
    PORT
      LAYER M5 ;
        RECT 61.0080 220.2360 61.0320 220.3200 ;
    END
  END f_d[209]
  PIN f_d[210]
    DIRECTION INPUT ;
    USE SIGNAL ;
    PORT
      LAYER M5 ;
        RECT 61.2480 220.2360 61.2720 220.3200 ;
    END
  END f_d[210]
  PIN f_d[211]
    DIRECTION INPUT ;
    USE SIGNAL ;
    PORT
      LAYER M5 ;
        RECT 61.4880 220.2360 61.5120 220.3200 ;
    END
  END f_d[211]
  PIN f_d[212]
    DIRECTION INPUT ;
    USE SIGNAL ;
    PORT
      LAYER M5 ;
        RECT 61.6800 220.2360 61.7040 220.3200 ;
    END
  END f_d[212]
  PIN f_d[213]
    DIRECTION INPUT ;
    USE SIGNAL ;
    PORT
      LAYER M5 ;
        RECT 61.9200 220.2360 61.9440 220.3200 ;
    END
  END f_d[213]
  PIN f_d[214]
    DIRECTION INPUT ;
    USE SIGNAL ;
    PORT
      LAYER M5 ;
        RECT 62.1600 220.2360 62.1840 220.3200 ;
    END
  END f_d[214]
  PIN f_d[215]
    DIRECTION INPUT ;
    USE SIGNAL ;
    PORT
      LAYER M5 ;
        RECT 62.4000 220.2360 62.4240 220.3200 ;
    END
  END f_d[215]
  PIN f_d[216]
    DIRECTION INPUT ;
    USE SIGNAL ;
    PORT
      LAYER M5 ;
        RECT 62.6400 220.2360 62.6640 220.3200 ;
    END
  END f_d[216]
  PIN f_d[217]
    DIRECTION INPUT ;
    USE SIGNAL ;
    PORT
      LAYER M5 ;
        RECT 62.8320 220.2360 62.8560 220.3200 ;
    END
  END f_d[217]
  PIN f_d[218]
    DIRECTION INPUT ;
    USE SIGNAL ;
    PORT
      LAYER M5 ;
        RECT 63.0720 220.2360 63.0960 220.3200 ;
    END
  END f_d[218]
  PIN f_d[219]
    DIRECTION INPUT ;
    USE SIGNAL ;
    PORT
      LAYER M5 ;
        RECT 63.3120 220.2360 63.3360 220.3200 ;
    END
  END f_d[219]
  PIN f_d[220]
    DIRECTION INPUT ;
    USE SIGNAL ;
    PORT
      LAYER M5 ;
        RECT 63.5520 220.2360 63.5760 220.3200 ;
    END
  END f_d[220]
  PIN f_d[221]
    DIRECTION INPUT ;
    USE SIGNAL ;
    PORT
      LAYER M5 ;
        RECT 63.7440 220.2360 63.7680 220.3200 ;
    END
  END f_d[221]
  PIN f_d[222]
    DIRECTION INPUT ;
    USE SIGNAL ;
    PORT
      LAYER M5 ;
        RECT 63.9840 220.2360 64.0080 220.3200 ;
    END
  END f_d[222]
  PIN f_d[223]
    DIRECTION INPUT ;
    USE SIGNAL ;
    PORT
      LAYER M5 ;
        RECT 64.2240 220.2360 64.2480 220.3200 ;
    END
  END f_d[223]
  PIN f_d[224]
    DIRECTION INPUT ;
    USE SIGNAL ;
    PORT
      LAYER M5 ;
        RECT 64.4640 220.2360 64.4880 220.3200 ;
    END
  END f_d[224]
  PIN f_d[225]
    DIRECTION INPUT ;
    USE SIGNAL ;
    PORT
      LAYER M5 ;
        RECT 64.7040 220.2360 64.7280 220.3200 ;
    END
  END f_d[225]
  PIN f_d[226]
    DIRECTION INPUT ;
    USE SIGNAL ;
    PORT
      LAYER M5 ;
        RECT 64.8960 220.2360 64.9200 220.3200 ;
    END
  END f_d[226]
  PIN f_d[227]
    DIRECTION INPUT ;
    USE SIGNAL ;
    PORT
      LAYER M5 ;
        RECT 65.1360 220.2360 65.1600 220.3200 ;
    END
  END f_d[227]
  PIN f_d[228]
    DIRECTION INPUT ;
    USE SIGNAL ;
    PORT
      LAYER M5 ;
        RECT 65.3760 220.2360 65.4000 220.3200 ;
    END
  END f_d[228]
  PIN f_d[229]
    DIRECTION INPUT ;
    USE SIGNAL ;
    PORT
      LAYER M5 ;
        RECT 65.6160 220.2360 65.6400 220.3200 ;
    END
  END f_d[229]
  PIN f_d[230]
    DIRECTION INPUT ;
    USE SIGNAL ;
    PORT
      LAYER M5 ;
        RECT 65.8560 220.2360 65.8800 220.3200 ;
    END
  END f_d[230]
  PIN f_d[231]
    DIRECTION INPUT ;
    USE SIGNAL ;
    PORT
      LAYER M5 ;
        RECT 66.0480 220.2360 66.0720 220.3200 ;
    END
  END f_d[231]
  PIN f_d[232]
    DIRECTION INPUT ;
    USE SIGNAL ;
    PORT
      LAYER M5 ;
        RECT 66.2880 220.2360 66.3120 220.3200 ;
    END
  END f_d[232]
  PIN f_d[233]
    DIRECTION INPUT ;
    USE SIGNAL ;
    PORT
      LAYER M5 ;
        RECT 66.5280 220.2360 66.5520 220.3200 ;
    END
  END f_d[233]
  PIN f_d[234]
    DIRECTION INPUT ;
    USE SIGNAL ;
    PORT
      LAYER M5 ;
        RECT 66.7680 220.2360 66.7920 220.3200 ;
    END
  END f_d[234]
  PIN f_d[235]
    DIRECTION INPUT ;
    USE SIGNAL ;
    PORT
      LAYER M5 ;
        RECT 66.9600 220.2360 66.9840 220.3200 ;
    END
  END f_d[235]
  PIN f_d[236]
    DIRECTION INPUT ;
    USE SIGNAL ;
    PORT
      LAYER M5 ;
        RECT 67.2000 220.2360 67.2240 220.3200 ;
    END
  END f_d[236]
  PIN f_d[237]
    DIRECTION INPUT ;
    USE SIGNAL ;
    PORT
      LAYER M5 ;
        RECT 67.4400 220.2360 67.4640 220.3200 ;
    END
  END f_d[237]
  PIN f_d[238]
    DIRECTION INPUT ;
    USE SIGNAL ;
    PORT
      LAYER M5 ;
        RECT 67.6800 220.2360 67.7040 220.3200 ;
    END
  END f_d[238]
  PIN f_d[239]
    DIRECTION INPUT ;
    USE SIGNAL ;
    PORT
      LAYER M5 ;
        RECT 67.9200 220.2360 67.9440 220.3200 ;
    END
  END f_d[239]
  PIN clk
    DIRECTION INPUT ;
    USE SIGNAL ;
    PORT
      LAYER M5 ;
        RECT 68.1120 220.2360 68.1360 220.3200 ;
    END
  END clk
  PIN rst_n
    DIRECTION INPUT ;
    USE SIGNAL ;
    PORT
      LAYER M5 ;
        RECT 68.3520 220.2360 68.3760 220.3200 ;
    END
  END rst_n
  PIN f_d[240]
    DIRECTION INPUT ;
    USE SIGNAL ;
    PORT
      LAYER M5 ;
        RECT 68.5920 220.2360 68.6160 220.3200 ;
    END
  END f_d[240]
  PIN f_d[241]
    DIRECTION INPUT ;
    USE SIGNAL ;
    PORT
      LAYER M5 ;
        RECT 68.8320 220.2360 68.8560 220.3200 ;
    END
  END f_d[241]
  PIN f_d[242]
    DIRECTION INPUT ;
    USE SIGNAL ;
    PORT
      LAYER M5 ;
        RECT 69.0240 220.2360 69.0480 220.3200 ;
    END
  END f_d[242]
  PIN f_d[243]
    DIRECTION INPUT ;
    USE SIGNAL ;
    PORT
      LAYER M5 ;
        RECT 69.2640 220.2360 69.2880 220.3200 ;
    END
  END f_d[243]
  PIN f_d[244]
    DIRECTION INPUT ;
    USE SIGNAL ;
    PORT
      LAYER M5 ;
        RECT 69.5040 220.2360 69.5280 220.3200 ;
    END
  END f_d[244]
  PIN f_d[245]
    DIRECTION INPUT ;
    USE SIGNAL ;
    PORT
      LAYER M5 ;
        RECT 69.7440 220.2360 69.7680 220.3200 ;
    END
  END f_d[245]
  PIN f_d[246]
    DIRECTION INPUT ;
    USE SIGNAL ;
    PORT
      LAYER M5 ;
        RECT 69.9840 220.2360 70.0080 220.3200 ;
    END
  END f_d[246]
  PIN f_d[247]
    DIRECTION INPUT ;
    USE SIGNAL ;
    PORT
      LAYER M5 ;
        RECT 70.1760 220.2360 70.2000 220.3200 ;
    END
  END f_d[247]
  PIN f_d[248]
    DIRECTION INPUT ;
    USE SIGNAL ;
    PORT
      LAYER M5 ;
        RECT 70.4160 220.2360 70.4400 220.3200 ;
    END
  END f_d[248]
  PIN f_d[249]
    DIRECTION INPUT ;
    USE SIGNAL ;
    PORT
      LAYER M5 ;
        RECT 70.6560 220.2360 70.6800 220.3200 ;
    END
  END f_d[249]
  PIN f_d[250]
    DIRECTION INPUT ;
    USE SIGNAL ;
    PORT
      LAYER M5 ;
        RECT 70.8960 220.2360 70.9200 220.3200 ;
    END
  END f_d[250]
  PIN f_d[251]
    DIRECTION INPUT ;
    USE SIGNAL ;
    PORT
      LAYER M5 ;
        RECT 71.1360 220.2360 71.1600 220.3200 ;
    END
  END f_d[251]
  PIN f_d[252]
    DIRECTION INPUT ;
    USE SIGNAL ;
    PORT
      LAYER M5 ;
        RECT 71.3280 220.2360 71.3520 220.3200 ;
    END
  END f_d[252]
  PIN f_d[253]
    DIRECTION INPUT ;
    USE SIGNAL ;
    PORT
      LAYER M5 ;
        RECT 71.5680 220.2360 71.5920 220.3200 ;
    END
  END f_d[253]
  PIN f_d[254]
    DIRECTION INPUT ;
    USE SIGNAL ;
    PORT
      LAYER M5 ;
        RECT 71.8080 220.2360 71.8320 220.3200 ;
    END
  END f_d[254]
  PIN f_d[255]
    DIRECTION INPUT ;
    USE SIGNAL ;
    PORT
      LAYER M5 ;
        RECT 72.0480 220.2360 72.0720 220.3200 ;
    END
  END f_d[255]
  PIN f_d[256]
    DIRECTION INPUT ;
    USE SIGNAL ;
    PORT
      LAYER M5 ;
        RECT 72.2400 220.2360 72.2640 220.3200 ;
    END
  END f_d[256]
  PIN f_d[257]
    DIRECTION INPUT ;
    USE SIGNAL ;
    PORT
      LAYER M5 ;
        RECT 72.4800 220.2360 72.5040 220.3200 ;
    END
  END f_d[257]
  PIN f_d[258]
    DIRECTION INPUT ;
    USE SIGNAL ;
    PORT
      LAYER M5 ;
        RECT 72.7200 220.2360 72.7440 220.3200 ;
    END
  END f_d[258]
  PIN f_d[259]
    DIRECTION INPUT ;
    USE SIGNAL ;
    PORT
      LAYER M5 ;
        RECT 72.9600 220.2360 72.9840 220.3200 ;
    END
  END f_d[259]
  PIN f_d[260]
    DIRECTION INPUT ;
    USE SIGNAL ;
    PORT
      LAYER M5 ;
        RECT 73.2000 220.2360 73.2240 220.3200 ;
    END
  END f_d[260]
  PIN f_d[261]
    DIRECTION INPUT ;
    USE SIGNAL ;
    PORT
      LAYER M5 ;
        RECT 73.3920 220.2360 73.4160 220.3200 ;
    END
  END f_d[261]
  PIN f_d[262]
    DIRECTION INPUT ;
    USE SIGNAL ;
    PORT
      LAYER M5 ;
        RECT 73.6320 220.2360 73.6560 220.3200 ;
    END
  END f_d[262]
  PIN f_d[263]
    DIRECTION INPUT ;
    USE SIGNAL ;
    PORT
      LAYER M5 ;
        RECT 73.8720 220.2360 73.8960 220.3200 ;
    END
  END f_d[263]
  PIN f_d[264]
    DIRECTION INPUT ;
    USE SIGNAL ;
    PORT
      LAYER M5 ;
        RECT 74.1120 220.2360 74.1360 220.3200 ;
    END
  END f_d[264]
  PIN f_d[265]
    DIRECTION INPUT ;
    USE SIGNAL ;
    PORT
      LAYER M5 ;
        RECT 74.3040 220.2360 74.3280 220.3200 ;
    END
  END f_d[265]
  PIN f_d[266]
    DIRECTION INPUT ;
    USE SIGNAL ;
    PORT
      LAYER M5 ;
        RECT 74.5440 220.2360 74.5680 220.3200 ;
    END
  END f_d[266]
  PIN f_d[267]
    DIRECTION INPUT ;
    USE SIGNAL ;
    PORT
      LAYER M5 ;
        RECT 74.7840 220.2360 74.8080 220.3200 ;
    END
  END f_d[267]
  PIN f_d[268]
    DIRECTION INPUT ;
    USE SIGNAL ;
    PORT
      LAYER M5 ;
        RECT 75.0240 220.2360 75.0480 220.3200 ;
    END
  END f_d[268]
  PIN f_d[269]
    DIRECTION INPUT ;
    USE SIGNAL ;
    PORT
      LAYER M5 ;
        RECT 75.2640 220.2360 75.2880 220.3200 ;
    END
  END f_d[269]
  PIN f_d[270]
    DIRECTION INPUT ;
    USE SIGNAL ;
    PORT
      LAYER M5 ;
        RECT 75.4560 220.2360 75.4800 220.3200 ;
    END
  END f_d[270]
  PIN f_d[271]
    DIRECTION INPUT ;
    USE SIGNAL ;
    PORT
      LAYER M5 ;
        RECT 75.6960 220.2360 75.7200 220.3200 ;
    END
  END f_d[271]
  PIN f_d[272]
    DIRECTION INPUT ;
    USE SIGNAL ;
    PORT
      LAYER M5 ;
        RECT 75.9360 220.2360 75.9600 220.3200 ;
    END
  END f_d[272]
  PIN f_d[273]
    DIRECTION INPUT ;
    USE SIGNAL ;
    PORT
      LAYER M5 ;
        RECT 76.1760 220.2360 76.2000 220.3200 ;
    END
  END f_d[273]
  PIN f_d[274]
    DIRECTION INPUT ;
    USE SIGNAL ;
    PORT
      LAYER M5 ;
        RECT 76.3680 220.2360 76.3920 220.3200 ;
    END
  END f_d[274]
  PIN f_d[275]
    DIRECTION INPUT ;
    USE SIGNAL ;
    PORT
      LAYER M5 ;
        RECT 76.6080 220.2360 76.6320 220.3200 ;
    END
  END f_d[275]
  PIN f_d[276]
    DIRECTION INPUT ;
    USE SIGNAL ;
    PORT
      LAYER M5 ;
        RECT 76.8480 220.2360 76.8720 220.3200 ;
    END
  END f_d[276]
  PIN f_d[277]
    DIRECTION INPUT ;
    USE SIGNAL ;
    PORT
      LAYER M5 ;
        RECT 77.0880 220.2360 77.1120 220.3200 ;
    END
  END f_d[277]
  PIN f_d[278]
    DIRECTION INPUT ;
    USE SIGNAL ;
    PORT
      LAYER M5 ;
        RECT 77.3280 220.2360 77.3520 220.3200 ;
    END
  END f_d[278]
  PIN f_d[279]
    DIRECTION INPUT ;
    USE SIGNAL ;
    PORT
      LAYER M5 ;
        RECT 77.5200 220.2360 77.5440 220.3200 ;
    END
  END f_d[279]
  PIN f_d[280]
    DIRECTION INPUT ;
    USE SIGNAL ;
    PORT
      LAYER M5 ;
        RECT 77.7600 220.2360 77.7840 220.3200 ;
    END
  END f_d[280]
  PIN f_d[281]
    DIRECTION INPUT ;
    USE SIGNAL ;
    PORT
      LAYER M5 ;
        RECT 78.0000 220.2360 78.0240 220.3200 ;
    END
  END f_d[281]
  PIN f_d[282]
    DIRECTION INPUT ;
    USE SIGNAL ;
    PORT
      LAYER M5 ;
        RECT 78.2400 220.2360 78.2640 220.3200 ;
    END
  END f_d[282]
  PIN f_d[283]
    DIRECTION INPUT ;
    USE SIGNAL ;
    PORT
      LAYER M5 ;
        RECT 78.4800 220.2360 78.5040 220.3200 ;
    END
  END f_d[283]
  PIN f_d[284]
    DIRECTION INPUT ;
    USE SIGNAL ;
    PORT
      LAYER M5 ;
        RECT 78.6720 220.2360 78.6960 220.3200 ;
    END
  END f_d[284]
  PIN f_d[285]
    DIRECTION INPUT ;
    USE SIGNAL ;
    PORT
      LAYER M5 ;
        RECT 78.9120 220.2360 78.9360 220.3200 ;
    END
  END f_d[285]
  PIN f_d[286]
    DIRECTION INPUT ;
    USE SIGNAL ;
    PORT
      LAYER M5 ;
        RECT 79.1520 220.2360 79.1760 220.3200 ;
    END
  END f_d[286]
  PIN f_d[287]
    DIRECTION INPUT ;
    USE SIGNAL ;
    PORT
      LAYER M5 ;
        RECT 79.3920 220.2360 79.4160 220.3200 ;
    END
  END f_d[287]
  PIN f_d[288]
    DIRECTION INPUT ;
    USE SIGNAL ;
    PORT
      LAYER M5 ;
        RECT 79.5840 220.2360 79.6080 220.3200 ;
    END
  END f_d[288]
  PIN f_d[289]
    DIRECTION INPUT ;
    USE SIGNAL ;
    PORT
      LAYER M5 ;
        RECT 79.8240 220.2360 79.8480 220.3200 ;
    END
  END f_d[289]
  PIN f_d[290]
    DIRECTION INPUT ;
    USE SIGNAL ;
    PORT
      LAYER M5 ;
        RECT 80.0640 220.2360 80.0880 220.3200 ;
    END
  END f_d[290]
  PIN f_d[291]
    DIRECTION INPUT ;
    USE SIGNAL ;
    PORT
      LAYER M5 ;
        RECT 80.3040 220.2360 80.3280 220.3200 ;
    END
  END f_d[291]
  PIN f_d[292]
    DIRECTION INPUT ;
    USE SIGNAL ;
    PORT
      LAYER M5 ;
        RECT 80.5440 220.2360 80.5680 220.3200 ;
    END
  END f_d[292]
  PIN f_d[293]
    DIRECTION INPUT ;
    USE SIGNAL ;
    PORT
      LAYER M5 ;
        RECT 80.7360 220.2360 80.7600 220.3200 ;
    END
  END f_d[293]
  PIN f_d[294]
    DIRECTION INPUT ;
    USE SIGNAL ;
    PORT
      LAYER M5 ;
        RECT 80.9760 220.2360 81.0000 220.3200 ;
    END
  END f_d[294]
  PIN f_d[295]
    DIRECTION INPUT ;
    USE SIGNAL ;
    PORT
      LAYER M5 ;
        RECT 81.2160 220.2360 81.2400 220.3200 ;
    END
  END f_d[295]
  PIN f_d[296]
    DIRECTION INPUT ;
    USE SIGNAL ;
    PORT
      LAYER M5 ;
        RECT 81.4560 220.2360 81.4800 220.3200 ;
    END
  END f_d[296]
  PIN f_d[297]
    DIRECTION INPUT ;
    USE SIGNAL ;
    PORT
      LAYER M5 ;
        RECT 81.6480 220.2360 81.6720 220.3200 ;
    END
  END f_d[297]
  PIN f_d[298]
    DIRECTION INPUT ;
    USE SIGNAL ;
    PORT
      LAYER M5 ;
        RECT 81.8880 220.2360 81.9120 220.3200 ;
    END
  END f_d[298]
  PIN f_d[299]
    DIRECTION INPUT ;
    USE SIGNAL ;
    PORT
      LAYER M5 ;
        RECT 82.1280 220.2360 82.1520 220.3200 ;
    END
  END f_d[299]
  PIN f_d[300]
    DIRECTION INPUT ;
    USE SIGNAL ;
    PORT
      LAYER M5 ;
        RECT 82.3680 220.2360 82.3920 220.3200 ;
    END
  END f_d[300]
  PIN f_d[301]
    DIRECTION INPUT ;
    USE SIGNAL ;
    PORT
      LAYER M5 ;
        RECT 82.6080 220.2360 82.6320 220.3200 ;
    END
  END f_d[301]
  PIN f_d[302]
    DIRECTION INPUT ;
    USE SIGNAL ;
    PORT
      LAYER M5 ;
        RECT 82.8000 220.2360 82.8240 220.3200 ;
    END
  END f_d[302]
  PIN f_d[303]
    DIRECTION INPUT ;
    USE SIGNAL ;
    PORT
      LAYER M5 ;
        RECT 83.0400 220.2360 83.0640 220.3200 ;
    END
  END f_d[303]
  PIN f_d[304]
    DIRECTION INPUT ;
    USE SIGNAL ;
    PORT
      LAYER M5 ;
        RECT 83.2800 220.2360 83.3040 220.3200 ;
    END
  END f_d[304]
  PIN f_d[305]
    DIRECTION INPUT ;
    USE SIGNAL ;
    PORT
      LAYER M5 ;
        RECT 83.5200 220.2360 83.5440 220.3200 ;
    END
  END f_d[305]
  PIN f_d[306]
    DIRECTION INPUT ;
    USE SIGNAL ;
    PORT
      LAYER M5 ;
        RECT 83.7600 220.2360 83.7840 220.3200 ;
    END
  END f_d[306]
  PIN f_d[307]
    DIRECTION INPUT ;
    USE SIGNAL ;
    PORT
      LAYER M5 ;
        RECT 83.9520 220.2360 83.9760 220.3200 ;
    END
  END f_d[307]
  PIN f_d[308]
    DIRECTION INPUT ;
    USE SIGNAL ;
    PORT
      LAYER M5 ;
        RECT 84.1920 220.2360 84.2160 220.3200 ;
    END
  END f_d[308]
  PIN f_d[309]
    DIRECTION INPUT ;
    USE SIGNAL ;
    PORT
      LAYER M5 ;
        RECT 84.4320 220.2360 84.4560 220.3200 ;
    END
  END f_d[309]
  PIN f_d[310]
    DIRECTION INPUT ;
    USE SIGNAL ;
    PORT
      LAYER M5 ;
        RECT 84.6720 220.2360 84.6960 220.3200 ;
    END
  END f_d[310]
  PIN f_d[311]
    DIRECTION INPUT ;
    USE SIGNAL ;
    PORT
      LAYER M5 ;
        RECT 84.8640 220.2360 84.8880 220.3200 ;
    END
  END f_d[311]
  PIN f_d[312]
    DIRECTION INPUT ;
    USE SIGNAL ;
    PORT
      LAYER M5 ;
        RECT 85.1040 220.2360 85.1280 220.3200 ;
    END
  END f_d[312]
  PIN f_d[313]
    DIRECTION INPUT ;
    USE SIGNAL ;
    PORT
      LAYER M5 ;
        RECT 85.3440 220.2360 85.3680 220.3200 ;
    END
  END f_d[313]
  PIN f_d[314]
    DIRECTION INPUT ;
    USE SIGNAL ;
    PORT
      LAYER M5 ;
        RECT 85.5840 220.2360 85.6080 220.3200 ;
    END
  END f_d[314]
  PIN f_d[315]
    DIRECTION INPUT ;
    USE SIGNAL ;
    PORT
      LAYER M5 ;
        RECT 85.8240 220.2360 85.8480 220.3200 ;
    END
  END f_d[315]
  PIN f_d[316]
    DIRECTION INPUT ;
    USE SIGNAL ;
    PORT
      LAYER M5 ;
        RECT 86.0160 220.2360 86.0400 220.3200 ;
    END
  END f_d[316]
  PIN f_d[317]
    DIRECTION INPUT ;
    USE SIGNAL ;
    PORT
      LAYER M5 ;
        RECT 86.2560 220.2360 86.2800 220.3200 ;
    END
  END f_d[317]
  PIN f_d[318]
    DIRECTION INPUT ;
    USE SIGNAL ;
    PORT
      LAYER M5 ;
        RECT 86.4960 220.2360 86.5200 220.3200 ;
    END
  END f_d[318]
  PIN f_d[319]
    DIRECTION INPUT ;
    USE SIGNAL ;
    PORT
      LAYER M5 ;
        RECT 86.7360 220.2360 86.7600 220.3200 ;
    END
  END f_d[319]
  PIN f_d[320]
    DIRECTION INPUT ;
    USE SIGNAL ;
    PORT
      LAYER M5 ;
        RECT 86.9280 220.2360 86.9520 220.3200 ;
    END
  END f_d[320]
  PIN f_d[321]
    DIRECTION INPUT ;
    USE SIGNAL ;
    PORT
      LAYER M5 ;
        RECT 87.1680 220.2360 87.1920 220.3200 ;
    END
  END f_d[321]
  PIN f_d[322]
    DIRECTION INPUT ;
    USE SIGNAL ;
    PORT
      LAYER M5 ;
        RECT 87.4080 220.2360 87.4320 220.3200 ;
    END
  END f_d[322]
  PIN f_d[323]
    DIRECTION INPUT ;
    USE SIGNAL ;
    PORT
      LAYER M5 ;
        RECT 87.6480 220.2360 87.6720 220.3200 ;
    END
  END f_d[323]
  PIN f_d[324]
    DIRECTION INPUT ;
    USE SIGNAL ;
    PORT
      LAYER M5 ;
        RECT 87.8880 220.2360 87.9120 220.3200 ;
    END
  END f_d[324]
  PIN f_d[325]
    DIRECTION INPUT ;
    USE SIGNAL ;
    PORT
      LAYER M5 ;
        RECT 88.0800 220.2360 88.1040 220.3200 ;
    END
  END f_d[325]
  PIN f_d[326]
    DIRECTION INPUT ;
    USE SIGNAL ;
    PORT
      LAYER M5 ;
        RECT 88.3200 220.2360 88.3440 220.3200 ;
    END
  END f_d[326]
  PIN f_d[327]
    DIRECTION INPUT ;
    USE SIGNAL ;
    PORT
      LAYER M5 ;
        RECT 88.5600 220.2360 88.5840 220.3200 ;
    END
  END f_d[327]
  PIN f_d[328]
    DIRECTION INPUT ;
    USE SIGNAL ;
    PORT
      LAYER M5 ;
        RECT 88.8000 220.2360 88.8240 220.3200 ;
    END
  END f_d[328]
  PIN f_d[329]
    DIRECTION INPUT ;
    USE SIGNAL ;
    PORT
      LAYER M5 ;
        RECT 88.9920 220.2360 89.0160 220.3200 ;
    END
  END f_d[329]
  PIN f_d[330]
    DIRECTION INPUT ;
    USE SIGNAL ;
    PORT
      LAYER M5 ;
        RECT 89.2320 220.2360 89.2560 220.3200 ;
    END
  END f_d[330]
  PIN f_d[331]
    DIRECTION INPUT ;
    USE SIGNAL ;
    PORT
      LAYER M5 ;
        RECT 89.4720 220.2360 89.4960 220.3200 ;
    END
  END f_d[331]
  PIN f_d[332]
    DIRECTION INPUT ;
    USE SIGNAL ;
    PORT
      LAYER M5 ;
        RECT 89.7120 220.2360 89.7360 220.3200 ;
    END
  END f_d[332]
  PIN f_d[333]
    DIRECTION INPUT ;
    USE SIGNAL ;
    PORT
      LAYER M5 ;
        RECT 89.9520 220.2360 89.9760 220.3200 ;
    END
  END f_d[333]
  PIN f_d[334]
    DIRECTION INPUT ;
    USE SIGNAL ;
    PORT
      LAYER M5 ;
        RECT 90.1440 220.2360 90.1680 220.3200 ;
    END
  END f_d[334]
  PIN f_d[335]
    DIRECTION INPUT ;
    USE SIGNAL ;
    PORT
      LAYER M5 ;
        RECT 90.3840 220.2360 90.4080 220.3200 ;
    END
  END f_d[335]
  PIN f_d[336]
    DIRECTION INPUT ;
    USE SIGNAL ;
    PORT
      LAYER M5 ;
        RECT 90.6240 220.2360 90.6480 220.3200 ;
    END
  END f_d[336]
  PIN f_d[337]
    DIRECTION INPUT ;
    USE SIGNAL ;
    PORT
      LAYER M5 ;
        RECT 90.8640 220.2360 90.8880 220.3200 ;
    END
  END f_d[337]
  PIN f_d[338]
    DIRECTION INPUT ;
    USE SIGNAL ;
    PORT
      LAYER M5 ;
        RECT 91.1040 220.2360 91.1280 220.3200 ;
    END
  END f_d[338]
  PIN f_d[339]
    DIRECTION INPUT ;
    USE SIGNAL ;
    PORT
      LAYER M5 ;
        RECT 91.2960 220.2360 91.3200 220.3200 ;
    END
  END f_d[339]
  PIN f_d[340]
    DIRECTION INPUT ;
    USE SIGNAL ;
    PORT
      LAYER M5 ;
        RECT 91.5360 220.2360 91.5600 220.3200 ;
    END
  END f_d[340]
  PIN f_d[341]
    DIRECTION INPUT ;
    USE SIGNAL ;
    PORT
      LAYER M5 ;
        RECT 91.7760 220.2360 91.8000 220.3200 ;
    END
  END f_d[341]
  PIN f_d[342]
    DIRECTION INPUT ;
    USE SIGNAL ;
    PORT
      LAYER M5 ;
        RECT 92.0160 220.2360 92.0400 220.3200 ;
    END
  END f_d[342]
  PIN f_d[343]
    DIRECTION INPUT ;
    USE SIGNAL ;
    PORT
      LAYER M5 ;
        RECT 92.2080 220.2360 92.2320 220.3200 ;
    END
  END f_d[343]
  PIN f_d[344]
    DIRECTION INPUT ;
    USE SIGNAL ;
    PORT
      LAYER M5 ;
        RECT 92.4480 220.2360 92.4720 220.3200 ;
    END
  END f_d[344]
  PIN f_d[345]
    DIRECTION INPUT ;
    USE SIGNAL ;
    PORT
      LAYER M5 ;
        RECT 92.6880 220.2360 92.7120 220.3200 ;
    END
  END f_d[345]
  PIN f_d[346]
    DIRECTION INPUT ;
    USE SIGNAL ;
    PORT
      LAYER M5 ;
        RECT 92.9280 220.2360 92.9520 220.3200 ;
    END
  END f_d[346]
  PIN f_d[347]
    DIRECTION INPUT ;
    USE SIGNAL ;
    PORT
      LAYER M5 ;
        RECT 93.1680 220.2360 93.1920 220.3200 ;
    END
  END f_d[347]
  PIN f_d[348]
    DIRECTION INPUT ;
    USE SIGNAL ;
    PORT
      LAYER M5 ;
        RECT 93.3600 220.2360 93.3840 220.3200 ;
    END
  END f_d[348]
  PIN f_d[349]
    DIRECTION INPUT ;
    USE SIGNAL ;
    PORT
      LAYER M5 ;
        RECT 93.6000 220.2360 93.6240 220.3200 ;
    END
  END f_d[349]
  PIN f_d[350]
    DIRECTION INPUT ;
    USE SIGNAL ;
    PORT
      LAYER M5 ;
        RECT 93.8400 220.2360 93.8640 220.3200 ;
    END
  END f_d[350]
  PIN f_d[351]
    DIRECTION INPUT ;
    USE SIGNAL ;
    PORT
      LAYER M5 ;
        RECT 94.0800 220.2360 94.1040 220.3200 ;
    END
  END f_d[351]
  PIN f_d[352]
    DIRECTION INPUT ;
    USE SIGNAL ;
    PORT
      LAYER M5 ;
        RECT 94.2720 220.2360 94.2960 220.3200 ;
    END
  END f_d[352]
  PIN f_d[353]
    DIRECTION INPUT ;
    USE SIGNAL ;
    PORT
      LAYER M5 ;
        RECT 94.5120 220.2360 94.5360 220.3200 ;
    END
  END f_d[353]
  PIN f_d[354]
    DIRECTION INPUT ;
    USE SIGNAL ;
    PORT
      LAYER M5 ;
        RECT 94.7520 220.2360 94.7760 220.3200 ;
    END
  END f_d[354]
  PIN f_d[355]
    DIRECTION INPUT ;
    USE SIGNAL ;
    PORT
      LAYER M5 ;
        RECT 94.9920 220.2360 95.0160 220.3200 ;
    END
  END f_d[355]
  PIN f_d[356]
    DIRECTION INPUT ;
    USE SIGNAL ;
    PORT
      LAYER M5 ;
        RECT 95.2320 220.2360 95.2560 220.3200 ;
    END
  END f_d[356]
  PIN f_d[357]
    DIRECTION INPUT ;
    USE SIGNAL ;
    PORT
      LAYER M5 ;
        RECT 95.4240 220.2360 95.4480 220.3200 ;
    END
  END f_d[357]
  PIN f_d[358]
    DIRECTION INPUT ;
    USE SIGNAL ;
    PORT
      LAYER M5 ;
        RECT 95.6640 220.2360 95.6880 220.3200 ;
    END
  END f_d[358]
  PIN f_d[359]
    DIRECTION INPUT ;
    USE SIGNAL ;
    PORT
      LAYER M5 ;
        RECT 95.9040 220.2360 95.9280 220.3200 ;
    END
  END f_d[359]
  PIN f_d[360]
    DIRECTION INPUT ;
    USE SIGNAL ;
    PORT
      LAYER M5 ;
        RECT 96.1440 220.2360 96.1680 220.3200 ;
    END
  END f_d[360]
  PIN f_d[361]
    DIRECTION INPUT ;
    USE SIGNAL ;
    PORT
      LAYER M5 ;
        RECT 96.3840 220.2360 96.4080 220.3200 ;
    END
  END f_d[361]
  PIN f_d[362]
    DIRECTION INPUT ;
    USE SIGNAL ;
    PORT
      LAYER M5 ;
        RECT 96.5760 220.2360 96.6000 220.3200 ;
    END
  END f_d[362]
  PIN f_d[363]
    DIRECTION INPUT ;
    USE SIGNAL ;
    PORT
      LAYER M5 ;
        RECT 96.8160 220.2360 96.8400 220.3200 ;
    END
  END f_d[363]
  PIN f_d[364]
    DIRECTION INPUT ;
    USE SIGNAL ;
    PORT
      LAYER M5 ;
        RECT 97.0560 220.2360 97.0800 220.3200 ;
    END
  END f_d[364]
  PIN f_d[365]
    DIRECTION INPUT ;
    USE SIGNAL ;
    PORT
      LAYER M5 ;
        RECT 97.2960 220.2360 97.3200 220.3200 ;
    END
  END f_d[365]
  PIN f_d[366]
    DIRECTION INPUT ;
    USE SIGNAL ;
    PORT
      LAYER M5 ;
        RECT 97.4880 220.2360 97.5120 220.3200 ;
    END
  END f_d[366]
  PIN f_d[367]
    DIRECTION INPUT ;
    USE SIGNAL ;
    PORT
      LAYER M5 ;
        RECT 97.7280 220.2360 97.7520 220.3200 ;
    END
  END f_d[367]
  PIN f_d[368]
    DIRECTION INPUT ;
    USE SIGNAL ;
    PORT
      LAYER M5 ;
        RECT 97.9680 220.2360 97.9920 220.3200 ;
    END
  END f_d[368]
  PIN f_d[369]
    DIRECTION INPUT ;
    USE SIGNAL ;
    PORT
      LAYER M5 ;
        RECT 98.2080 220.2360 98.2320 220.3200 ;
    END
  END f_d[369]
  PIN f_d[370]
    DIRECTION INPUT ;
    USE SIGNAL ;
    PORT
      LAYER M5 ;
        RECT 98.4480 220.2360 98.4720 220.3200 ;
    END
  END f_d[370]
  PIN f_d[371]
    DIRECTION INPUT ;
    USE SIGNAL ;
    PORT
      LAYER M5 ;
        RECT 98.6400 220.2360 98.6640 220.3200 ;
    END
  END f_d[371]
  PIN f_d[372]
    DIRECTION INPUT ;
    USE SIGNAL ;
    PORT
      LAYER M5 ;
        RECT 98.8800 220.2360 98.9040 220.3200 ;
    END
  END f_d[372]
  PIN f_d[373]
    DIRECTION INPUT ;
    USE SIGNAL ;
    PORT
      LAYER M5 ;
        RECT 99.1200 220.2360 99.1440 220.3200 ;
    END
  END f_d[373]
  PIN f_d[374]
    DIRECTION INPUT ;
    USE SIGNAL ;
    PORT
      LAYER M5 ;
        RECT 99.3600 220.2360 99.3840 220.3200 ;
    END
  END f_d[374]
  PIN f_d[375]
    DIRECTION INPUT ;
    USE SIGNAL ;
    PORT
      LAYER M5 ;
        RECT 99.5520 220.2360 99.5760 220.3200 ;
    END
  END f_d[375]
  PIN f_d[376]
    DIRECTION INPUT ;
    USE SIGNAL ;
    PORT
      LAYER M5 ;
        RECT 99.7920 220.2360 99.8160 220.3200 ;
    END
  END f_d[376]
  PIN f_d[377]
    DIRECTION INPUT ;
    USE SIGNAL ;
    PORT
      LAYER M5 ;
        RECT 100.0320 220.2360 100.0560 220.3200 ;
    END
  END f_d[377]
  PIN f_d[378]
    DIRECTION INPUT ;
    USE SIGNAL ;
    PORT
      LAYER M5 ;
        RECT 100.2720 220.2360 100.2960 220.3200 ;
    END
  END f_d[378]
  PIN f_d[379]
    DIRECTION INPUT ;
    USE SIGNAL ;
    PORT
      LAYER M5 ;
        RECT 100.5120 220.2360 100.5360 220.3200 ;
    END
  END f_d[379]
  PIN f_d[380]
    DIRECTION INPUT ;
    USE SIGNAL ;
    PORT
      LAYER M5 ;
        RECT 100.7040 220.2360 100.7280 220.3200 ;
    END
  END f_d[380]
  PIN f_d[381]
    DIRECTION INPUT ;
    USE SIGNAL ;
    PORT
      LAYER M5 ;
        RECT 100.9440 220.2360 100.9680 220.3200 ;
    END
  END f_d[381]
  PIN f_d[382]
    DIRECTION INPUT ;
    USE SIGNAL ;
    PORT
      LAYER M5 ;
        RECT 101.1840 220.2360 101.2080 220.3200 ;
    END
  END f_d[382]
  PIN f_d[383]
    DIRECTION INPUT ;
    USE SIGNAL ;
    PORT
      LAYER M5 ;
        RECT 101.4240 220.2360 101.4480 220.3200 ;
    END
  END f_d[383]
  PIN f_d[384]
    DIRECTION INPUT ;
    USE SIGNAL ;
    PORT
      LAYER M5 ;
        RECT 101.6160 220.2360 101.6400 220.3200 ;
    END
  END f_d[384]
  PIN f_d[385]
    DIRECTION INPUT ;
    USE SIGNAL ;
    PORT
      LAYER M5 ;
        RECT 101.8560 220.2360 101.8800 220.3200 ;
    END
  END f_d[385]
  PIN f_d[386]
    DIRECTION INPUT ;
    USE SIGNAL ;
    PORT
      LAYER M5 ;
        RECT 102.0960 220.2360 102.1200 220.3200 ;
    END
  END f_d[386]
  PIN f_d[387]
    DIRECTION INPUT ;
    USE SIGNAL ;
    PORT
      LAYER M5 ;
        RECT 102.3360 220.2360 102.3600 220.3200 ;
    END
  END f_d[387]
  PIN f_d[388]
    DIRECTION INPUT ;
    USE SIGNAL ;
    PORT
      LAYER M5 ;
        RECT 102.5760 220.2360 102.6000 220.3200 ;
    END
  END f_d[388]
  PIN f_d[389]
    DIRECTION INPUT ;
    USE SIGNAL ;
    PORT
      LAYER M5 ;
        RECT 102.7680 220.2360 102.7920 220.3200 ;
    END
  END f_d[389]
  PIN f_d[390]
    DIRECTION INPUT ;
    USE SIGNAL ;
    PORT
      LAYER M5 ;
        RECT 103.0080 220.2360 103.0320 220.3200 ;
    END
  END f_d[390]
  PIN f_d[391]
    DIRECTION INPUT ;
    USE SIGNAL ;
    PORT
      LAYER M5 ;
        RECT 103.2480 220.2360 103.2720 220.3200 ;
    END
  END f_d[391]
  PIN f_d[392]
    DIRECTION INPUT ;
    USE SIGNAL ;
    PORT
      LAYER M5 ;
        RECT 103.4880 220.2360 103.5120 220.3200 ;
    END
  END f_d[392]
  PIN f_d[393]
    DIRECTION INPUT ;
    USE SIGNAL ;
    PORT
      LAYER M5 ;
        RECT 103.7280 220.2360 103.7520 220.3200 ;
    END
  END f_d[393]
  PIN f_d[394]
    DIRECTION INPUT ;
    USE SIGNAL ;
    PORT
      LAYER M5 ;
        RECT 103.9200 220.2360 103.9440 220.3200 ;
    END
  END f_d[394]
  PIN f_d[395]
    DIRECTION INPUT ;
    USE SIGNAL ;
    PORT
      LAYER M5 ;
        RECT 104.1600 220.2360 104.1840 220.3200 ;
    END
  END f_d[395]
  PIN f_d[396]
    DIRECTION INPUT ;
    USE SIGNAL ;
    PORT
      LAYER M5 ;
        RECT 104.4000 220.2360 104.4240 220.3200 ;
    END
  END f_d[396]
  PIN f_d[397]
    DIRECTION INPUT ;
    USE SIGNAL ;
    PORT
      LAYER M5 ;
        RECT 104.6400 220.2360 104.6640 220.3200 ;
    END
  END f_d[397]
  PIN f_d[398]
    DIRECTION INPUT ;
    USE SIGNAL ;
    PORT
      LAYER M5 ;
        RECT 104.8320 220.2360 104.8560 220.3200 ;
    END
  END f_d[398]
  PIN f_d[399]
    DIRECTION INPUT ;
    USE SIGNAL ;
    PORT
      LAYER M5 ;
        RECT 105.0720 220.2360 105.0960 220.3200 ;
    END
  END f_d[399]
  PIN f_d[400]
    DIRECTION INPUT ;
    USE SIGNAL ;
    PORT
      LAYER M5 ;
        RECT 105.3120 220.2360 105.3360 220.3200 ;
    END
  END f_d[400]
  PIN f_d[401]
    DIRECTION INPUT ;
    USE SIGNAL ;
    PORT
      LAYER M5 ;
        RECT 105.5520 220.2360 105.5760 220.3200 ;
    END
  END f_d[401]
  PIN f_d[402]
    DIRECTION INPUT ;
    USE SIGNAL ;
    PORT
      LAYER M5 ;
        RECT 105.7920 220.2360 105.8160 220.3200 ;
    END
  END f_d[402]
  PIN f_d[403]
    DIRECTION INPUT ;
    USE SIGNAL ;
    PORT
      LAYER M5 ;
        RECT 105.9840 220.2360 106.0080 220.3200 ;
    END
  END f_d[403]
  PIN f_d[404]
    DIRECTION INPUT ;
    USE SIGNAL ;
    PORT
      LAYER M5 ;
        RECT 106.2240 220.2360 106.2480 220.3200 ;
    END
  END f_d[404]
  PIN f_d[405]
    DIRECTION INPUT ;
    USE SIGNAL ;
    PORT
      LAYER M5 ;
        RECT 106.4640 220.2360 106.4880 220.3200 ;
    END
  END f_d[405]
  PIN f_d[406]
    DIRECTION INPUT ;
    USE SIGNAL ;
    PORT
      LAYER M5 ;
        RECT 106.7040 220.2360 106.7280 220.3200 ;
    END
  END f_d[406]
  PIN f_d[407]
    DIRECTION INPUT ;
    USE SIGNAL ;
    PORT
      LAYER M5 ;
        RECT 106.8960 220.2360 106.9200 220.3200 ;
    END
  END f_d[407]
  PIN f_d[408]
    DIRECTION INPUT ;
    USE SIGNAL ;
    PORT
      LAYER M5 ;
        RECT 107.1360 220.2360 107.1600 220.3200 ;
    END
  END f_d[408]
  PIN f_d[409]
    DIRECTION INPUT ;
    USE SIGNAL ;
    PORT
      LAYER M5 ;
        RECT 107.3760 220.2360 107.4000 220.3200 ;
    END
  END f_d[409]
  PIN f_d[410]
    DIRECTION INPUT ;
    USE SIGNAL ;
    PORT
      LAYER M5 ;
        RECT 107.6160 220.2360 107.6400 220.3200 ;
    END
  END f_d[410]
  PIN f_d[411]
    DIRECTION INPUT ;
    USE SIGNAL ;
    PORT
      LAYER M5 ;
        RECT 107.8560 220.2360 107.8800 220.3200 ;
    END
  END f_d[411]
  PIN f_d[412]
    DIRECTION INPUT ;
    USE SIGNAL ;
    PORT
      LAYER M5 ;
        RECT 108.0480 220.2360 108.0720 220.3200 ;
    END
  END f_d[412]
  PIN f_d[413]
    DIRECTION INPUT ;
    USE SIGNAL ;
    PORT
      LAYER M5 ;
        RECT 108.2880 220.2360 108.3120 220.3200 ;
    END
  END f_d[413]
  PIN f_d[414]
    DIRECTION INPUT ;
    USE SIGNAL ;
    PORT
      LAYER M5 ;
        RECT 108.5280 220.2360 108.5520 220.3200 ;
    END
  END f_d[414]
  PIN f_d[415]
    DIRECTION INPUT ;
    USE SIGNAL ;
    PORT
      LAYER M5 ;
        RECT 108.7680 220.2360 108.7920 220.3200 ;
    END
  END f_d[415]
  PIN f_d[416]
    DIRECTION INPUT ;
    USE SIGNAL ;
    PORT
      LAYER M5 ;
        RECT 109.0080 220.2360 109.0320 220.3200 ;
    END
  END f_d[416]
  PIN f_d[417]
    DIRECTION INPUT ;
    USE SIGNAL ;
    PORT
      LAYER M5 ;
        RECT 109.2000 220.2360 109.2240 220.3200 ;
    END
  END f_d[417]
  PIN f_d[418]
    DIRECTION INPUT ;
    USE SIGNAL ;
    PORT
      LAYER M5 ;
        RECT 109.4400 220.2360 109.4640 220.3200 ;
    END
  END f_d[418]
  PIN f_d[419]
    DIRECTION INPUT ;
    USE SIGNAL ;
    PORT
      LAYER M5 ;
        RECT 109.6800 220.2360 109.7040 220.3200 ;
    END
  END f_d[419]
  PIN f_d[420]
    DIRECTION INPUT ;
    USE SIGNAL ;
    PORT
      LAYER M5 ;
        RECT 109.9200 220.2360 109.9440 220.3200 ;
    END
  END f_d[420]
  PIN f_d[421]
    DIRECTION INPUT ;
    USE SIGNAL ;
    PORT
      LAYER M5 ;
        RECT 110.1120 220.2360 110.1360 220.3200 ;
    END
  END f_d[421]
  PIN f_d[422]
    DIRECTION INPUT ;
    USE SIGNAL ;
    PORT
      LAYER M5 ;
        RECT 110.3520 220.2360 110.3760 220.3200 ;
    END
  END f_d[422]
  PIN f_d[423]
    DIRECTION INPUT ;
    USE SIGNAL ;
    PORT
      LAYER M5 ;
        RECT 110.5920 220.2360 110.6160 220.3200 ;
    END
  END f_d[423]
  PIN f_d[424]
    DIRECTION INPUT ;
    USE SIGNAL ;
    PORT
      LAYER M5 ;
        RECT 110.8320 220.2360 110.8560 220.3200 ;
    END
  END f_d[424]
  PIN f_d[425]
    DIRECTION INPUT ;
    USE SIGNAL ;
    PORT
      LAYER M5 ;
        RECT 111.0720 220.2360 111.0960 220.3200 ;
    END
  END f_d[425]
  PIN f_d[426]
    DIRECTION INPUT ;
    USE SIGNAL ;
    PORT
      LAYER M5 ;
        RECT 111.2640 220.2360 111.2880 220.3200 ;
    END
  END f_d[426]
  PIN f_d[427]
    DIRECTION INPUT ;
    USE SIGNAL ;
    PORT
      LAYER M5 ;
        RECT 111.5040 220.2360 111.5280 220.3200 ;
    END
  END f_d[427]
  PIN f_d[428]
    DIRECTION INPUT ;
    USE SIGNAL ;
    PORT
      LAYER M5 ;
        RECT 111.7440 220.2360 111.7680 220.3200 ;
    END
  END f_d[428]
  PIN f_d[429]
    DIRECTION INPUT ;
    USE SIGNAL ;
    PORT
      LAYER M5 ;
        RECT 111.9840 220.2360 112.0080 220.3200 ;
    END
  END f_d[429]
  PIN f_d[430]
    DIRECTION INPUT ;
    USE SIGNAL ;
    PORT
      LAYER M5 ;
        RECT 112.1760 220.2360 112.2000 220.3200 ;
    END
  END f_d[430]
  PIN f_d[431]
    DIRECTION INPUT ;
    USE SIGNAL ;
    PORT
      LAYER M5 ;
        RECT 112.4160 220.2360 112.4400 220.3200 ;
    END
  END f_d[431]
  PIN f_d[432]
    DIRECTION INPUT ;
    USE SIGNAL ;
    PORT
      LAYER M5 ;
        RECT 112.6560 220.2360 112.6800 220.3200 ;
    END
  END f_d[432]
  PIN f_d[433]
    DIRECTION INPUT ;
    USE SIGNAL ;
    PORT
      LAYER M5 ;
        RECT 112.8960 220.2360 112.9200 220.3200 ;
    END
  END f_d[433]
  PIN f_d[434]
    DIRECTION INPUT ;
    USE SIGNAL ;
    PORT
      LAYER M5 ;
        RECT 113.1360 220.2360 113.1600 220.3200 ;
    END
  END f_d[434]
  PIN f_d[435]
    DIRECTION INPUT ;
    USE SIGNAL ;
    PORT
      LAYER M5 ;
        RECT 113.3280 220.2360 113.3520 220.3200 ;
    END
  END f_d[435]
  PIN f_d[436]
    DIRECTION INPUT ;
    USE SIGNAL ;
    PORT
      LAYER M5 ;
        RECT 113.5680 220.2360 113.5920 220.3200 ;
    END
  END f_d[436]
  PIN f_d[437]
    DIRECTION INPUT ;
    USE SIGNAL ;
    PORT
      LAYER M5 ;
        RECT 113.8080 220.2360 113.8320 220.3200 ;
    END
  END f_d[437]
  PIN f_d[438]
    DIRECTION INPUT ;
    USE SIGNAL ;
    PORT
      LAYER M5 ;
        RECT 114.0480 220.2360 114.0720 220.3200 ;
    END
  END f_d[438]
  PIN f_d[439]
    DIRECTION INPUT ;
    USE SIGNAL ;
    PORT
      LAYER M5 ;
        RECT 114.2400 220.2360 114.2640 220.3200 ;
    END
  END f_d[439]
  PIN f_d[440]
    DIRECTION INPUT ;
    USE SIGNAL ;
    PORT
      LAYER M5 ;
        RECT 114.4800 220.2360 114.5040 220.3200 ;
    END
  END f_d[440]
  PIN f_d[441]
    DIRECTION INPUT ;
    USE SIGNAL ;
    PORT
      LAYER M5 ;
        RECT 114.7200 220.2360 114.7440 220.3200 ;
    END
  END f_d[441]
  PIN f_d[442]
    DIRECTION INPUT ;
    USE SIGNAL ;
    PORT
      LAYER M5 ;
        RECT 114.9600 220.2360 114.9840 220.3200 ;
    END
  END f_d[442]
  PIN f_d[443]
    DIRECTION INPUT ;
    USE SIGNAL ;
    PORT
      LAYER M5 ;
        RECT 115.2000 220.2360 115.2240 220.3200 ;
    END
  END f_d[443]
  PIN f_d[444]
    DIRECTION INPUT ;
    USE SIGNAL ;
    PORT
      LAYER M5 ;
        RECT 115.3920 220.2360 115.4160 220.3200 ;
    END
  END f_d[444]
  PIN f_d[445]
    DIRECTION INPUT ;
    USE SIGNAL ;
    PORT
      LAYER M5 ;
        RECT 115.6320 220.2360 115.6560 220.3200 ;
    END
  END f_d[445]
  PIN f_d[446]
    DIRECTION INPUT ;
    USE SIGNAL ;
    PORT
      LAYER M5 ;
        RECT 115.8720 220.2360 115.8960 220.3200 ;
    END
  END f_d[446]
  PIN f_d[447]
    DIRECTION INPUT ;
    USE SIGNAL ;
    PORT
      LAYER M5 ;
        RECT 116.1120 220.2360 116.1360 220.3200 ;
    END
  END f_d[447]
  PIN f_d[448]
    DIRECTION INPUT ;
    USE SIGNAL ;
    PORT
      LAYER M5 ;
        RECT 116.3520 220.2360 116.3760 220.3200 ;
    END
  END f_d[448]
  PIN f_d[449]
    DIRECTION INPUT ;
    USE SIGNAL ;
    PORT
      LAYER M5 ;
        RECT 116.5440 220.2360 116.5680 220.3200 ;
    END
  END f_d[449]
  PIN f_d[450]
    DIRECTION INPUT ;
    USE SIGNAL ;
    PORT
      LAYER M5 ;
        RECT 116.7840 220.2360 116.8080 220.3200 ;
    END
  END f_d[450]
  PIN f_d[451]
    DIRECTION INPUT ;
    USE SIGNAL ;
    PORT
      LAYER M5 ;
        RECT 117.0240 220.2360 117.0480 220.3200 ;
    END
  END f_d[451]
  PIN f_d[452]
    DIRECTION INPUT ;
    USE SIGNAL ;
    PORT
      LAYER M5 ;
        RECT 117.2640 220.2360 117.2880 220.3200 ;
    END
  END f_d[452]
  PIN f_d[453]
    DIRECTION INPUT ;
    USE SIGNAL ;
    PORT
      LAYER M5 ;
        RECT 117.4560 220.2360 117.4800 220.3200 ;
    END
  END f_d[453]
  PIN f_d[454]
    DIRECTION INPUT ;
    USE SIGNAL ;
    PORT
      LAYER M5 ;
        RECT 117.6960 220.2360 117.7200 220.3200 ;
    END
  END f_d[454]
  PIN f_d[455]
    DIRECTION INPUT ;
    USE SIGNAL ;
    PORT
      LAYER M5 ;
        RECT 117.9360 220.2360 117.9600 220.3200 ;
    END
  END f_d[455]
  PIN f_d[456]
    DIRECTION INPUT ;
    USE SIGNAL ;
    PORT
      LAYER M5 ;
        RECT 118.1760 220.2360 118.2000 220.3200 ;
    END
  END f_d[456]
  PIN f_d[457]
    DIRECTION INPUT ;
    USE SIGNAL ;
    PORT
      LAYER M5 ;
        RECT 118.4160 220.2360 118.4400 220.3200 ;
    END
  END f_d[457]
  PIN f_d[458]
    DIRECTION INPUT ;
    USE SIGNAL ;
    PORT
      LAYER M5 ;
        RECT 118.6080 220.2360 118.6320 220.3200 ;
    END
  END f_d[458]
  PIN f_d[459]
    DIRECTION INPUT ;
    USE SIGNAL ;
    PORT
      LAYER M5 ;
        RECT 118.8480 220.2360 118.8720 220.3200 ;
    END
  END f_d[459]
  PIN f_d[460]
    DIRECTION INPUT ;
    USE SIGNAL ;
    PORT
      LAYER M5 ;
        RECT 119.0880 220.2360 119.1120 220.3200 ;
    END
  END f_d[460]
  PIN f_d[461]
    DIRECTION INPUT ;
    USE SIGNAL ;
    PORT
      LAYER M5 ;
        RECT 119.3280 220.2360 119.3520 220.3200 ;
    END
  END f_d[461]
  PIN f_d[462]
    DIRECTION INPUT ;
    USE SIGNAL ;
    PORT
      LAYER M5 ;
        RECT 119.5200 220.2360 119.5440 220.3200 ;
    END
  END f_d[462]
  PIN f_d[463]
    DIRECTION INPUT ;
    USE SIGNAL ;
    PORT
      LAYER M5 ;
        RECT 119.7600 220.2360 119.7840 220.3200 ;
    END
  END f_d[463]
  PIN f_d[464]
    DIRECTION INPUT ;
    USE SIGNAL ;
    PORT
      LAYER M5 ;
        RECT 120.0000 220.2360 120.0240 220.3200 ;
    END
  END f_d[464]
  PIN f_d[465]
    DIRECTION INPUT ;
    USE SIGNAL ;
    PORT
      LAYER M5 ;
        RECT 120.2400 220.2360 120.2640 220.3200 ;
    END
  END f_d[465]
  PIN f_d[466]
    DIRECTION INPUT ;
    USE SIGNAL ;
    PORT
      LAYER M5 ;
        RECT 120.4800 220.2360 120.5040 220.3200 ;
    END
  END f_d[466]
  PIN f_d[467]
    DIRECTION INPUT ;
    USE SIGNAL ;
    PORT
      LAYER M5 ;
        RECT 120.6720 220.2360 120.6960 220.3200 ;
    END
  END f_d[467]
  PIN f_d[468]
    DIRECTION INPUT ;
    USE SIGNAL ;
    PORT
      LAYER M5 ;
        RECT 120.9120 220.2360 120.9360 220.3200 ;
    END
  END f_d[468]
  PIN f_d[469]
    DIRECTION INPUT ;
    USE SIGNAL ;
    PORT
      LAYER M5 ;
        RECT 121.1520 220.2360 121.1760 220.3200 ;
    END
  END f_d[469]
  PIN f_d[470]
    DIRECTION INPUT ;
    USE SIGNAL ;
    PORT
      LAYER M5 ;
        RECT 121.3920 220.2360 121.4160 220.3200 ;
    END
  END f_d[470]
  PIN f_d[471]
    DIRECTION INPUT ;
    USE SIGNAL ;
    PORT
      LAYER M5 ;
        RECT 121.6320 220.2360 121.6560 220.3200 ;
    END
  END f_d[471]
  PIN f_d[472]
    DIRECTION INPUT ;
    USE SIGNAL ;
    PORT
      LAYER M5 ;
        RECT 121.8240 220.2360 121.8480 220.3200 ;
    END
  END f_d[472]
  PIN f_d[473]
    DIRECTION INPUT ;
    USE SIGNAL ;
    PORT
      LAYER M5 ;
        RECT 122.0640 220.2360 122.0880 220.3200 ;
    END
  END f_d[473]
  PIN f_d[474]
    DIRECTION INPUT ;
    USE SIGNAL ;
    PORT
      LAYER M5 ;
        RECT 122.3040 220.2360 122.3280 220.3200 ;
    END
  END f_d[474]
  PIN f_d[475]
    DIRECTION INPUT ;
    USE SIGNAL ;
    PORT
      LAYER M5 ;
        RECT 122.5440 220.2360 122.5680 220.3200 ;
    END
  END f_d[475]
  PIN f_d[476]
    DIRECTION INPUT ;
    USE SIGNAL ;
    PORT
      LAYER M5 ;
        RECT 122.7360 220.2360 122.7600 220.3200 ;
    END
  END f_d[476]
  PIN f_d[477]
    DIRECTION INPUT ;
    USE SIGNAL ;
    PORT
      LAYER M5 ;
        RECT 122.9760 220.2360 123.0000 220.3200 ;
    END
  END f_d[477]
  PIN f_d[478]
    DIRECTION INPUT ;
    USE SIGNAL ;
    PORT
      LAYER M5 ;
        RECT 123.2160 220.2360 123.2400 220.3200 ;
    END
  END f_d[478]
  PIN f_d[479]
    DIRECTION INPUT ;
    USE SIGNAL ;
    PORT
      LAYER M5 ;
        RECT 123.4560 220.2360 123.4800 220.3200 ;
    END
  END f_d[479]
  PIN r_v[0]
    DIRECTION OUTPUT ;
    USE SIGNAL ;
    PORT
      LAYER M5 ;
        RECT 123.6960 220.2360 123.7200 220.3200 ;
    END
  END r_v[0]
  PIN r_v[1]
    DIRECTION OUTPUT ;
    USE SIGNAL ;
    PORT
      LAYER M5 ;
        RECT 123.8880 220.2360 123.9120 220.3200 ;
    END
  END r_v[1]
  PIN r_hh[0]
    DIRECTION OUTPUT ;
    USE SIGNAL ;
    PORT
      LAYER M5 ;
        RECT 124.1280 220.2360 124.1520 220.3200 ;
    END
  END r_hh[0]
  PIN r_hh[1]
    DIRECTION OUTPUT ;
    USE SIGNAL ;
    PORT
      LAYER M5 ;
        RECT 124.3680 220.2360 124.3920 220.3200 ;
    END
  END r_hh[1]
  PIN r_hh[2]
    DIRECTION OUTPUT ;
    USE SIGNAL ;
    PORT
      LAYER M5 ;
        RECT 124.6080 220.2360 124.6320 220.3200 ;
    END
  END r_hh[2]
  PIN r_hh[3]
    DIRECTION OUTPUT ;
    USE SIGNAL ;
    PORT
      LAYER M5 ;
        RECT 124.8000 220.2360 124.8240 220.3200 ;
    END
  END r_hh[3]
  PIN r_hh[4]
    DIRECTION OUTPUT ;
    USE SIGNAL ;
    PORT
      LAYER M5 ;
        RECT 125.0400 220.2360 125.0640 220.3200 ;
    END
  END r_hh[4]
  PIN r_hh[5]
    DIRECTION OUTPUT ;
    USE SIGNAL ;
    PORT
      LAYER M5 ;
        RECT 125.2800 220.2360 125.3040 220.3200 ;
    END
  END r_hh[5]
  PIN r_hh[6]
    DIRECTION OUTPUT ;
    USE SIGNAL ;
    PORT
      LAYER M5 ;
        RECT 125.5200 220.2360 125.5440 220.3200 ;
    END
  END r_hh[6]
  PIN r_hh[7]
    DIRECTION OUTPUT ;
    USE SIGNAL ;
    PORT
      LAYER M5 ;
        RECT 125.7600 220.2360 125.7840 220.3200 ;
    END
  END r_hh[7]
  PIN r_hh[8]
    DIRECTION OUTPUT ;
    USE SIGNAL ;
    PORT
      LAYER M5 ;
        RECT 125.9520 220.2360 125.9760 220.3200 ;
    END
  END r_hh[8]
  PIN r_hh[9]
    DIRECTION OUTPUT ;
    USE SIGNAL ;
    PORT
      LAYER M5 ;
        RECT 126.1920 220.2360 126.2160 220.3200 ;
    END
  END r_hh[9]
  PIN r_hh[10]
    DIRECTION OUTPUT ;
    USE SIGNAL ;
    PORT
      LAYER M5 ;
        RECT 126.4320 220.2360 126.4560 220.3200 ;
    END
  END r_hh[10]
  PIN r_hh[11]
    DIRECTION OUTPUT ;
    USE SIGNAL ;
    PORT
      LAYER M5 ;
        RECT 126.6720 220.2360 126.6960 220.3200 ;
    END
  END r_hh[11]
  PIN r_hh[12]
    DIRECTION OUTPUT ;
    USE SIGNAL ;
    PORT
      LAYER M5 ;
        RECT 126.8640 220.2360 126.8880 220.3200 ;
    END
  END r_hh[12]
  PIN r_hh[13]
    DIRECTION OUTPUT ;
    USE SIGNAL ;
    PORT
      LAYER M5 ;
        RECT 127.1040 220.2360 127.1280 220.3200 ;
    END
  END r_hh[13]
  PIN r_hh[14]
    DIRECTION OUTPUT ;
    USE SIGNAL ;
    PORT
      LAYER M5 ;
        RECT 127.3440 220.2360 127.3680 220.3200 ;
    END
  END r_hh[14]
  PIN r_hh[15]
    DIRECTION OUTPUT ;
    USE SIGNAL ;
    PORT
      LAYER M5 ;
        RECT 127.5840 220.2360 127.6080 220.3200 ;
    END
  END r_hh[15]
  PIN r_hh[16]
    DIRECTION OUTPUT ;
    USE SIGNAL ;
    PORT
      LAYER M5 ;
        RECT 127.8240 220.2360 127.8480 220.3200 ;
    END
  END r_hh[16]
  PIN r_hh[17]
    DIRECTION OUTPUT ;
    USE SIGNAL ;
    PORT
      LAYER M5 ;
        RECT 128.0160 220.2360 128.0400 220.3200 ;
    END
  END r_hh[17]
  PIN r_hh[18]
    DIRECTION OUTPUT ;
    USE SIGNAL ;
    PORT
      LAYER M5 ;
        RECT 128.2560 220.2360 128.2800 220.3200 ;
    END
  END r_hh[18]
  PIN r_hh[19]
    DIRECTION OUTPUT ;
    USE SIGNAL ;
    PORT
      LAYER M5 ;
        RECT 128.4960 220.2360 128.5200 220.3200 ;
    END
  END r_hh[19]
  PIN r_hh[20]
    DIRECTION OUTPUT ;
    USE SIGNAL ;
    PORT
      LAYER M5 ;
        RECT 128.7360 220.2360 128.7600 220.3200 ;
    END
  END r_hh[20]
  PIN r_hh[21]
    DIRECTION OUTPUT ;
    USE SIGNAL ;
    PORT
      LAYER M5 ;
        RECT 128.9760 220.2360 129.0000 220.3200 ;
    END
  END r_hh[21]
  PIN r_hh[22]
    DIRECTION OUTPUT ;
    USE SIGNAL ;
    PORT
      LAYER M5 ;
        RECT 129.1680 220.2360 129.1920 220.3200 ;
    END
  END r_hh[22]
  PIN r_hh[23]
    DIRECTION OUTPUT ;
    USE SIGNAL ;
    PORT
      LAYER M5 ;
        RECT 129.4080 220.2360 129.4320 220.3200 ;
    END
  END r_hh[23]
  PIN r_hh[24]
    DIRECTION OUTPUT ;
    USE SIGNAL ;
    PORT
      LAYER M5 ;
        RECT 129.6480 220.2360 129.6720 220.3200 ;
    END
  END r_hh[24]
  PIN r_hh[25]
    DIRECTION OUTPUT ;
    USE SIGNAL ;
    PORT
      LAYER M5 ;
        RECT 129.8880 220.2360 129.9120 220.3200 ;
    END
  END r_hh[25]
  PIN r_hh[26]
    DIRECTION OUTPUT ;
    USE SIGNAL ;
    PORT
      LAYER M5 ;
        RECT 130.0800 220.2360 130.1040 220.3200 ;
    END
  END r_hh[26]
  PIN r_hh[27]
    DIRECTION OUTPUT ;
    USE SIGNAL ;
    PORT
      LAYER M5 ;
        RECT 130.3200 220.2360 130.3440 220.3200 ;
    END
  END r_hh[27]
  PIN r_hh[28]
    DIRECTION OUTPUT ;
    USE SIGNAL ;
    PORT
      LAYER M5 ;
        RECT 130.5600 220.2360 130.5840 220.3200 ;
    END
  END r_hh[28]
  PIN r_hh[29]
    DIRECTION OUTPUT ;
    USE SIGNAL ;
    PORT
      LAYER M5 ;
        RECT 130.8000 220.2360 130.8240 220.3200 ;
    END
  END r_hh[29]
  PIN r_hh[30]
    DIRECTION OUTPUT ;
    USE SIGNAL ;
    PORT
      LAYER M5 ;
        RECT 131.0400 220.2360 131.0640 220.3200 ;
    END
  END r_hh[30]
  PIN r_hh[31]
    DIRECTION OUTPUT ;
    USE SIGNAL ;
    PORT
      LAYER M5 ;
        RECT 131.2320 220.2360 131.2560 220.3200 ;
    END
  END r_hh[31]
  PIN r_hh[32]
    DIRECTION OUTPUT ;
    USE SIGNAL ;
    PORT
      LAYER M5 ;
        RECT 131.4720 220.2360 131.4960 220.3200 ;
    END
  END r_hh[32]
  PIN r_hh[33]
    DIRECTION OUTPUT ;
    USE SIGNAL ;
    PORT
      LAYER M5 ;
        RECT 131.7120 220.2360 131.7360 220.3200 ;
    END
  END r_hh[33]
  PIN r_hh[34]
    DIRECTION OUTPUT ;
    USE SIGNAL ;
    PORT
      LAYER M5 ;
        RECT 131.9520 220.2360 131.9760 220.3200 ;
    END
  END r_hh[34]
  PIN r_hh[35]
    DIRECTION OUTPUT ;
    USE SIGNAL ;
    PORT
      LAYER M5 ;
        RECT 132.1440 220.2360 132.1680 220.3200 ;
    END
  END r_hh[35]
  PIN r_hh[36]
    DIRECTION OUTPUT ;
    USE SIGNAL ;
    PORT
      LAYER M5 ;
        RECT 132.3840 220.2360 132.4080 220.3200 ;
    END
  END r_hh[36]
  PIN r_hh[37]
    DIRECTION OUTPUT ;
    USE SIGNAL ;
    PORT
      LAYER M5 ;
        RECT 132.6240 220.2360 132.6480 220.3200 ;
    END
  END r_hh[37]
  PIN r_hh[38]
    DIRECTION OUTPUT ;
    USE SIGNAL ;
    PORT
      LAYER M5 ;
        RECT 132.8640 220.2360 132.8880 220.3200 ;
    END
  END r_hh[38]
  PIN r_hh[39]
    DIRECTION OUTPUT ;
    USE SIGNAL ;
    PORT
      LAYER M5 ;
        RECT 133.1040 220.2360 133.1280 220.3200 ;
    END
  END r_hh[39]
  PIN r_hh[40]
    DIRECTION OUTPUT ;
    USE SIGNAL ;
    PORT
      LAYER M5 ;
        RECT 133.2960 220.2360 133.3200 220.3200 ;
    END
  END r_hh[40]
  PIN r_hh[41]
    DIRECTION OUTPUT ;
    USE SIGNAL ;
    PORT
      LAYER M5 ;
        RECT 133.5360 220.2360 133.5600 220.3200 ;
    END
  END r_hh[41]
  PIN r_hh[42]
    DIRECTION OUTPUT ;
    USE SIGNAL ;
    PORT
      LAYER M5 ;
        RECT 133.7760 220.2360 133.8000 220.3200 ;
    END
  END r_hh[42]
  PIN r_hh[43]
    DIRECTION OUTPUT ;
    USE SIGNAL ;
    PORT
      LAYER M5 ;
        RECT 134.0160 220.2360 134.0400 220.3200 ;
    END
  END r_hh[43]
  PIN r_hh[44]
    DIRECTION OUTPUT ;
    USE SIGNAL ;
    PORT
      LAYER M5 ;
        RECT 134.2560 220.2360 134.2800 220.3200 ;
    END
  END r_hh[44]
  PIN r_hh[45]
    DIRECTION OUTPUT ;
    USE SIGNAL ;
    PORT
      LAYER M5 ;
        RECT 134.4480 220.2360 134.4720 220.3200 ;
    END
  END r_hh[45]
  PIN r_hh[46]
    DIRECTION OUTPUT ;
    USE SIGNAL ;
    PORT
      LAYER M5 ;
        RECT 134.6880 220.2360 134.7120 220.3200 ;
    END
  END r_hh[46]
  PIN r_hh[47]
    DIRECTION OUTPUT ;
    USE SIGNAL ;
    PORT
      LAYER M5 ;
        RECT 134.9280 220.2360 134.9520 220.3200 ;
    END
  END r_hh[47]
  PIN r_hh[48]
    DIRECTION OUTPUT ;
    USE SIGNAL ;
    PORT
      LAYER M5 ;
        RECT 135.1680 220.2360 135.1920 220.3200 ;
    END
  END r_hh[48]
  PIN r_hh[49]
    DIRECTION OUTPUT ;
    USE SIGNAL ;
    PORT
      LAYER M5 ;
        RECT 135.3600 220.2360 135.3840 220.3200 ;
    END
  END r_hh[49]
  PIN r_hh[50]
    DIRECTION OUTPUT ;
    USE SIGNAL ;
    PORT
      LAYER M5 ;
        RECT 135.6000 220.2360 135.6240 220.3200 ;
    END
  END r_hh[50]
  PIN r_hh[51]
    DIRECTION OUTPUT ;
    USE SIGNAL ;
    PORT
      LAYER M5 ;
        RECT 135.8400 220.2360 135.8640 220.3200 ;
    END
  END r_hh[51]
  PIN r_hh[52]
    DIRECTION OUTPUT ;
    USE SIGNAL ;
    PORT
      LAYER M5 ;
        RECT 136.0800 220.2360 136.1040 220.3200 ;
    END
  END r_hh[52]
  PIN r_hh[53]
    DIRECTION OUTPUT ;
    USE SIGNAL ;
    PORT
      LAYER M5 ;
        RECT 136.3200 220.2360 136.3440 220.3200 ;
    END
  END r_hh[53]
  PIN r_hh[54]
    DIRECTION OUTPUT ;
    USE SIGNAL ;
    PORT
      LAYER M5 ;
        RECT 136.5120 220.2360 136.5360 220.3200 ;
    END
  END r_hh[54]
  PIN r_hh[55]
    DIRECTION OUTPUT ;
    USE SIGNAL ;
    PORT
      LAYER M5 ;
        RECT 136.7520 220.2360 136.7760 220.3200 ;
    END
  END r_hh[55]
  PIN r_hh[56]
    DIRECTION OUTPUT ;
    USE SIGNAL ;
    PORT
      LAYER M5 ;
        RECT 136.9920 220.2360 137.0160 220.3200 ;
    END
  END r_hh[56]
  PIN r_hh[57]
    DIRECTION OUTPUT ;
    USE SIGNAL ;
    PORT
      LAYER M5 ;
        RECT 137.2320 220.2360 137.2560 220.3200 ;
    END
  END r_hh[57]
  PIN r_hh[58]
    DIRECTION OUTPUT ;
    USE SIGNAL ;
    PORT
      LAYER M5 ;
        RECT 137.4240 220.2360 137.4480 220.3200 ;
    END
  END r_hh[58]
  PIN r_hh[59]
    DIRECTION OUTPUT ;
    USE SIGNAL ;
    PORT
      LAYER M5 ;
        RECT 137.6640 220.2360 137.6880 220.3200 ;
    END
  END r_hh[59]
  PIN r_hh[60]
    DIRECTION OUTPUT ;
    USE SIGNAL ;
    PORT
      LAYER M5 ;
        RECT 137.9040 220.2360 137.9280 220.3200 ;
    END
  END r_hh[60]
  PIN r_hh[61]
    DIRECTION OUTPUT ;
    USE SIGNAL ;
    PORT
      LAYER M5 ;
        RECT 138.1440 220.2360 138.1680 220.3200 ;
    END
  END r_hh[61]
  PIN r_hh[62]
    DIRECTION OUTPUT ;
    USE SIGNAL ;
    PORT
      LAYER M5 ;
        RECT 138.3840 220.2360 138.4080 220.3200 ;
    END
  END r_hh[62]
  PIN r_hh[63]
    DIRECTION OUTPUT ;
    USE SIGNAL ;
    PORT
      LAYER M5 ;
        RECT 138.5760 220.2360 138.6000 220.3200 ;
    END
  END r_hh[63]
  PIN r_kk[0]
    DIRECTION OUTPUT ;
    USE SIGNAL ;
    PORT
      LAYER M5 ;
        RECT 138.8160 220.2360 138.8400 220.3200 ;
    END
  END r_kk[0]
  PIN r_kk[1]
    DIRECTION OUTPUT ;
    USE SIGNAL ;
    PORT
      LAYER M5 ;
        RECT 139.0560 220.2360 139.0800 220.3200 ;
    END
  END r_kk[1]
  PIN r_kk[2]
    DIRECTION OUTPUT ;
    USE SIGNAL ;
    PORT
      LAYER M5 ;
        RECT 139.2960 220.2360 139.3200 220.3200 ;
    END
  END r_kk[2]
  PIN r_kk[3]
    DIRECTION OUTPUT ;
    USE SIGNAL ;
    PORT
      LAYER M5 ;
        RECT 139.4880 220.2360 139.5120 220.3200 ;
    END
  END r_kk[3]
  PIN r_kk[4]
    DIRECTION OUTPUT ;
    USE SIGNAL ;
    PORT
      LAYER M5 ;
        RECT 139.7280 220.2360 139.7520 220.3200 ;
    END
  END r_kk[4]
  PIN r_kk[5]
    DIRECTION OUTPUT ;
    USE SIGNAL ;
    PORT
      LAYER M5 ;
        RECT 139.9680 220.2360 139.9920 220.3200 ;
    END
  END r_kk[5]
  PIN r_kk[6]
    DIRECTION OUTPUT ;
    USE SIGNAL ;
    PORT
      LAYER M5 ;
        RECT 140.2080 220.2360 140.2320 220.3200 ;
    END
  END r_kk[6]
  PIN r_kk[7]
    DIRECTION OUTPUT ;
    USE SIGNAL ;
    PORT
      LAYER M5 ;
        RECT 140.4480 220.2360 140.4720 220.3200 ;
    END
  END r_kk[7]
  PIN r_kk[8]
    DIRECTION OUTPUT ;
    USE SIGNAL ;
    PORT
      LAYER M5 ;
        RECT 140.6400 220.2360 140.6640 220.3200 ;
    END
  END r_kk[8]
  PIN r_kk[9]
    DIRECTION OUTPUT ;
    USE SIGNAL ;
    PORT
      LAYER M5 ;
        RECT 140.8800 220.2360 140.9040 220.3200 ;
    END
  END r_kk[9]
  PIN r_kk[10]
    DIRECTION OUTPUT ;
    USE SIGNAL ;
    PORT
      LAYER M5 ;
        RECT 141.1200 220.2360 141.1440 220.3200 ;
    END
  END r_kk[10]
  PIN r_kk[11]
    DIRECTION OUTPUT ;
    USE SIGNAL ;
    PORT
      LAYER M5 ;
        RECT 141.3600 220.2360 141.3840 220.3200 ;
    END
  END r_kk[11]
  PIN r_kk[12]
    DIRECTION OUTPUT ;
    USE SIGNAL ;
    PORT
      LAYER M5 ;
        RECT 141.6000 220.2360 141.6240 220.3200 ;
    END
  END r_kk[12]
  PIN r_kk[13]
    DIRECTION OUTPUT ;
    USE SIGNAL ;
    PORT
      LAYER M5 ;
        RECT 141.7920 220.2360 141.8160 220.3200 ;
    END
  END r_kk[13]
  PIN r_kk[14]
    DIRECTION OUTPUT ;
    USE SIGNAL ;
    PORT
      LAYER M5 ;
        RECT 142.0320 220.2360 142.0560 220.3200 ;
    END
  END r_kk[14]
  PIN r_kk[15]
    DIRECTION OUTPUT ;
    USE SIGNAL ;
    PORT
      LAYER M5 ;
        RECT 142.2720 220.2360 142.2960 220.3200 ;
    END
  END r_kk[15]
  PIN r_kk[16]
    DIRECTION OUTPUT ;
    USE SIGNAL ;
    PORT
      LAYER M5 ;
        RECT 142.5120 220.2360 142.5360 220.3200 ;
    END
  END r_kk[16]
  PIN r_kk[17]
    DIRECTION OUTPUT ;
    USE SIGNAL ;
    PORT
      LAYER M5 ;
        RECT 142.7040 220.2360 142.7280 220.3200 ;
    END
  END r_kk[17]
  PIN r_kk[18]
    DIRECTION OUTPUT ;
    USE SIGNAL ;
    PORT
      LAYER M5 ;
        RECT 142.9440 220.2360 142.9680 220.3200 ;
    END
  END r_kk[18]
  PIN r_kk[19]
    DIRECTION OUTPUT ;
    USE SIGNAL ;
    PORT
      LAYER M5 ;
        RECT 143.1840 220.2360 143.2080 220.3200 ;
    END
  END r_kk[19]
  PIN r_kk[20]
    DIRECTION OUTPUT ;
    USE SIGNAL ;
    PORT
      LAYER M5 ;
        RECT 143.4240 220.2360 143.4480 220.3200 ;
    END
  END r_kk[20]
  PIN r_kk[21]
    DIRECTION OUTPUT ;
    USE SIGNAL ;
    PORT
      LAYER M5 ;
        RECT 143.6640 220.2360 143.6880 220.3200 ;
    END
  END r_kk[21]
  PIN r_kk[22]
    DIRECTION OUTPUT ;
    USE SIGNAL ;
    PORT
      LAYER M5 ;
        RECT 143.8560 220.2360 143.8800 220.3200 ;
    END
  END r_kk[22]
  PIN r_kk[23]
    DIRECTION OUTPUT ;
    USE SIGNAL ;
    PORT
      LAYER M5 ;
        RECT 144.0960 220.2360 144.1200 220.3200 ;
    END
  END r_kk[23]
  PIN r_kk[24]
    DIRECTION OUTPUT ;
    USE SIGNAL ;
    PORT
      LAYER M5 ;
        RECT 144.3360 220.2360 144.3600 220.3200 ;
    END
  END r_kk[24]
  PIN r_kk[25]
    DIRECTION OUTPUT ;
    USE SIGNAL ;
    PORT
      LAYER M5 ;
        RECT 144.5760 220.2360 144.6000 220.3200 ;
    END
  END r_kk[25]
  PIN r_kk[26]
    DIRECTION OUTPUT ;
    USE SIGNAL ;
    PORT
      LAYER M5 ;
        RECT 144.7680 220.2360 144.7920 220.3200 ;
    END
  END r_kk[26]
  PIN r_kk[27]
    DIRECTION OUTPUT ;
    USE SIGNAL ;
    PORT
      LAYER M5 ;
        RECT 145.0080 220.2360 145.0320 220.3200 ;
    END
  END r_kk[27]
  PIN r_kk[28]
    DIRECTION OUTPUT ;
    USE SIGNAL ;
    PORT
      LAYER M5 ;
        RECT 145.2480 220.2360 145.2720 220.3200 ;
    END
  END r_kk[28]
  PIN r_kk[29]
    DIRECTION OUTPUT ;
    USE SIGNAL ;
    PORT
      LAYER M5 ;
        RECT 145.4880 220.2360 145.5120 220.3200 ;
    END
  END r_kk[29]
  PIN r_kk[30]
    DIRECTION OUTPUT ;
    USE SIGNAL ;
    PORT
      LAYER M5 ;
        RECT 145.7280 220.2360 145.7520 220.3200 ;
    END
  END r_kk[30]
  PIN r_kk[31]
    DIRECTION OUTPUT ;
    USE SIGNAL ;
    PORT
      LAYER M5 ;
        RECT 145.9200 220.2360 145.9440 220.3200 ;
    END
  END r_kk[31]
  PIN r_kk[32]
    DIRECTION OUTPUT ;
    USE SIGNAL ;
    PORT
      LAYER M5 ;
        RECT 146.1600 220.2360 146.1840 220.3200 ;
    END
  END r_kk[32]
  PIN r_kk[33]
    DIRECTION OUTPUT ;
    USE SIGNAL ;
    PORT
      LAYER M5 ;
        RECT 146.4000 220.2360 146.4240 220.3200 ;
    END
  END r_kk[33]
  PIN r_kk[34]
    DIRECTION OUTPUT ;
    USE SIGNAL ;
    PORT
      LAYER M5 ;
        RECT 146.6400 220.2360 146.6640 220.3200 ;
    END
  END r_kk[34]
  PIN r_kk[35]
    DIRECTION OUTPUT ;
    USE SIGNAL ;
    PORT
      LAYER M5 ;
        RECT 146.8800 220.2360 146.9040 220.3200 ;
    END
  END r_kk[35]
  PIN r_kk[36]
    DIRECTION OUTPUT ;
    USE SIGNAL ;
    PORT
      LAYER M5 ;
        RECT 147.0720 220.2360 147.0960 220.3200 ;
    END
  END r_kk[36]
  PIN r_kk[37]
    DIRECTION OUTPUT ;
    USE SIGNAL ;
    PORT
      LAYER M5 ;
        RECT 147.3120 220.2360 147.3360 220.3200 ;
    END
  END r_kk[37]
  PIN r_kk[38]
    DIRECTION OUTPUT ;
    USE SIGNAL ;
    PORT
      LAYER M5 ;
        RECT 147.5520 220.2360 147.5760 220.3200 ;
    END
  END r_kk[38]
  PIN r_kk[39]
    DIRECTION OUTPUT ;
    USE SIGNAL ;
    PORT
      LAYER M5 ;
        RECT 147.7920 220.2360 147.8160 220.3200 ;
    END
  END r_kk[39]
  PIN r_kk[40]
    DIRECTION OUTPUT ;
    USE SIGNAL ;
    PORT
      LAYER M5 ;
        RECT 147.9840 220.2360 148.0080 220.3200 ;
    END
  END r_kk[40]
  PIN r_kk[41]
    DIRECTION OUTPUT ;
    USE SIGNAL ;
    PORT
      LAYER M5 ;
        RECT 148.2240 220.2360 148.2480 220.3200 ;
    END
  END r_kk[41]
  PIN r_kk[42]
    DIRECTION OUTPUT ;
    USE SIGNAL ;
    PORT
      LAYER M5 ;
        RECT 148.4640 220.2360 148.4880 220.3200 ;
    END
  END r_kk[42]
  PIN r_kk[43]
    DIRECTION OUTPUT ;
    USE SIGNAL ;
    PORT
      LAYER M5 ;
        RECT 148.7040 220.2360 148.7280 220.3200 ;
    END
  END r_kk[43]
  PIN r_kk[44]
    DIRECTION OUTPUT ;
    USE SIGNAL ;
    PORT
      LAYER M5 ;
        RECT 148.9440 220.2360 148.9680 220.3200 ;
    END
  END r_kk[44]
  PIN r_kk[45]
    DIRECTION OUTPUT ;
    USE SIGNAL ;
    PORT
      LAYER M5 ;
        RECT 149.1360 220.2360 149.1600 220.3200 ;
    END
  END r_kk[45]
  PIN r_kk[46]
    DIRECTION OUTPUT ;
    USE SIGNAL ;
    PORT
      LAYER M5 ;
        RECT 149.3760 220.2360 149.4000 220.3200 ;
    END
  END r_kk[46]
  PIN r_kk[47]
    DIRECTION OUTPUT ;
    USE SIGNAL ;
    PORT
      LAYER M5 ;
        RECT 149.6160 220.2360 149.6400 220.3200 ;
    END
  END r_kk[47]
  PIN r_kk[48]
    DIRECTION OUTPUT ;
    USE SIGNAL ;
    PORT
      LAYER M5 ;
        RECT 149.8560 220.2360 149.8800 220.3200 ;
    END
  END r_kk[48]
  PIN r_kk[49]
    DIRECTION OUTPUT ;
    USE SIGNAL ;
    PORT
      LAYER M5 ;
        RECT 150.0480 220.2360 150.0720 220.3200 ;
    END
  END r_kk[49]
  PIN r_kk[50]
    DIRECTION OUTPUT ;
    USE SIGNAL ;
    PORT
      LAYER M5 ;
        RECT 150.2880 220.2360 150.3120 220.3200 ;
    END
  END r_kk[50]
  PIN r_kk[51]
    DIRECTION OUTPUT ;
    USE SIGNAL ;
    PORT
      LAYER M5 ;
        RECT 150.5280 220.2360 150.5520 220.3200 ;
    END
  END r_kk[51]
  PIN r_kk[52]
    DIRECTION OUTPUT ;
    USE SIGNAL ;
    PORT
      LAYER M5 ;
        RECT 150.7680 220.2360 150.7920 220.3200 ;
    END
  END r_kk[52]
  PIN r_kk[53]
    DIRECTION OUTPUT ;
    USE SIGNAL ;
    PORT
      LAYER M5 ;
        RECT 151.0080 220.2360 151.0320 220.3200 ;
    END
  END r_kk[53]
  PIN r_kk[54]
    DIRECTION OUTPUT ;
    USE SIGNAL ;
    PORT
      LAYER M5 ;
        RECT 151.2000 220.2360 151.2240 220.3200 ;
    END
  END r_kk[54]
  PIN r_kk[55]
    DIRECTION OUTPUT ;
    USE SIGNAL ;
    PORT
      LAYER M5 ;
        RECT 151.4400 220.2360 151.4640 220.3200 ;
    END
  END r_kk[55]
  PIN r_kk[56]
    DIRECTION OUTPUT ;
    USE SIGNAL ;
    PORT
      LAYER M5 ;
        RECT 151.6800 220.2360 151.7040 220.3200 ;
    END
  END r_kk[56]
  PIN r_kk[57]
    DIRECTION OUTPUT ;
    USE SIGNAL ;
    PORT
      LAYER M5 ;
        RECT 151.9200 220.2360 151.9440 220.3200 ;
    END
  END r_kk[57]
  PIN r_kk[58]
    DIRECTION OUTPUT ;
    USE SIGNAL ;
    PORT
      LAYER M5 ;
        RECT 152.1120 220.2360 152.1360 220.3200 ;
    END
  END r_kk[58]
  PIN r_kk[59]
    DIRECTION OUTPUT ;
    USE SIGNAL ;
    PORT
      LAYER M5 ;
        RECT 152.3520 220.2360 152.3760 220.3200 ;
    END
  END r_kk[59]
  PIN r_kk[60]
    DIRECTION OUTPUT ;
    USE SIGNAL ;
    PORT
      LAYER M5 ;
        RECT 152.5920 220.2360 152.6160 220.3200 ;
    END
  END r_kk[60]
  PIN r_kk[61]
    DIRECTION OUTPUT ;
    USE SIGNAL ;
    PORT
      LAYER M5 ;
        RECT 152.8320 220.2360 152.8560 220.3200 ;
    END
  END r_kk[61]
  PIN r_kk[62]
    DIRECTION OUTPUT ;
    USE SIGNAL ;
    PORT
      LAYER M5 ;
        RECT 153.0720 220.2360 153.0960 220.3200 ;
    END
  END r_kk[62]
  PIN r_kk[63]
    DIRECTION OUTPUT ;
    USE SIGNAL ;
    PORT
      LAYER M5 ;
        RECT 153.2640 220.2360 153.2880 220.3200 ;
    END
  END r_kk[63]
  PIN r_dd[0]
    DIRECTION OUTPUT ;
    USE SIGNAL ;
    PORT
      LAYER M5 ;
        RECT 153.5040 220.2360 153.5280 220.3200 ;
    END
  END r_dd[0]
  PIN r_dd[1]
    DIRECTION OUTPUT ;
    USE SIGNAL ;
    PORT
      LAYER M5 ;
        RECT 153.7440 220.2360 153.7680 220.3200 ;
    END
  END r_dd[1]
  PIN r_dd[2]
    DIRECTION OUTPUT ;
    USE SIGNAL ;
    PORT
      LAYER M5 ;
        RECT 153.9840 220.2360 154.0080 220.3200 ;
    END
  END r_dd[2]
  PIN r_dd[3]
    DIRECTION OUTPUT ;
    USE SIGNAL ;
    PORT
      LAYER M5 ;
        RECT 154.2240 220.2360 154.2480 220.3200 ;
    END
  END r_dd[3]
  PIN r_dd[4]
    DIRECTION OUTPUT ;
    USE SIGNAL ;
    PORT
      LAYER M5 ;
        RECT 154.4160 220.2360 154.4400 220.3200 ;
    END
  END r_dd[4]
  PIN r_dd[5]
    DIRECTION OUTPUT ;
    USE SIGNAL ;
    PORT
      LAYER M5 ;
        RECT 154.6560 220.2360 154.6800 220.3200 ;
    END
  END r_dd[5]
  PIN r_dd[6]
    DIRECTION OUTPUT ;
    USE SIGNAL ;
    PORT
      LAYER M5 ;
        RECT 154.8960 220.2360 154.9200 220.3200 ;
    END
  END r_dd[6]
  PIN r_dd[7]
    DIRECTION OUTPUT ;
    USE SIGNAL ;
    PORT
      LAYER M5 ;
        RECT 155.1360 220.2360 155.1600 220.3200 ;
    END
  END r_dd[7]
  PIN r_dd[8]
    DIRECTION OUTPUT ;
    USE SIGNAL ;
    PORT
      LAYER M5 ;
        RECT 155.3280 220.2360 155.3520 220.3200 ;
    END
  END r_dd[8]
  PIN r_dd[9]
    DIRECTION OUTPUT ;
    USE SIGNAL ;
    PORT
      LAYER M5 ;
        RECT 155.5680 220.2360 155.5920 220.3200 ;
    END
  END r_dd[9]
  PIN r_dd[10]
    DIRECTION OUTPUT ;
    USE SIGNAL ;
    PORT
      LAYER M5 ;
        RECT 155.8080 220.2360 155.8320 220.3200 ;
    END
  END r_dd[10]
  PIN r_dd[11]
    DIRECTION OUTPUT ;
    USE SIGNAL ;
    PORT
      LAYER M5 ;
        RECT 156.0480 220.2360 156.0720 220.3200 ;
    END
  END r_dd[11]
  PIN r_dd[12]
    DIRECTION OUTPUT ;
    USE SIGNAL ;
    PORT
      LAYER M5 ;
        RECT 156.2880 220.2360 156.3120 220.3200 ;
    END
  END r_dd[12]
  PIN r_dd[13]
    DIRECTION OUTPUT ;
    USE SIGNAL ;
    PORT
      LAYER M5 ;
        RECT 156.4800 220.2360 156.5040 220.3200 ;
    END
  END r_dd[13]
  PIN r_dd[14]
    DIRECTION OUTPUT ;
    USE SIGNAL ;
    PORT
      LAYER M5 ;
        RECT 156.7200 220.2360 156.7440 220.3200 ;
    END
  END r_dd[14]
  PIN r_dd[15]
    DIRECTION OUTPUT ;
    USE SIGNAL ;
    PORT
      LAYER M5 ;
        RECT 156.9600 220.2360 156.9840 220.3200 ;
    END
  END r_dd[15]
  PIN r_dd[16]
    DIRECTION OUTPUT ;
    USE SIGNAL ;
    PORT
      LAYER M5 ;
        RECT 157.2000 220.2360 157.2240 220.3200 ;
    END
  END r_dd[16]
  PIN r_dd[17]
    DIRECTION OUTPUT ;
    USE SIGNAL ;
    PORT
      LAYER M5 ;
        RECT 157.3920 220.2360 157.4160 220.3200 ;
    END
  END r_dd[17]
  PIN r_dd[18]
    DIRECTION OUTPUT ;
    USE SIGNAL ;
    PORT
      LAYER M5 ;
        RECT 157.6320 220.2360 157.6560 220.3200 ;
    END
  END r_dd[18]
  PIN r_dd[19]
    DIRECTION OUTPUT ;
    USE SIGNAL ;
    PORT
      LAYER M5 ;
        RECT 157.8720 220.2360 157.8960 220.3200 ;
    END
  END r_dd[19]
  PIN r_dd[20]
    DIRECTION OUTPUT ;
    USE SIGNAL ;
    PORT
      LAYER M5 ;
        RECT 158.1120 220.2360 158.1360 220.3200 ;
    END
  END r_dd[20]
  PIN r_dd[21]
    DIRECTION OUTPUT ;
    USE SIGNAL ;
    PORT
      LAYER M5 ;
        RECT 158.3520 220.2360 158.3760 220.3200 ;
    END
  END r_dd[21]
  PIN r_dd[22]
    DIRECTION OUTPUT ;
    USE SIGNAL ;
    PORT
      LAYER M5 ;
        RECT 158.5440 220.2360 158.5680 220.3200 ;
    END
  END r_dd[22]
  PIN r_dd[23]
    DIRECTION OUTPUT ;
    USE SIGNAL ;
    PORT
      LAYER M5 ;
        RECT 158.7840 220.2360 158.8080 220.3200 ;
    END
  END r_dd[23]
  PIN r_dd[24]
    DIRECTION OUTPUT ;
    USE SIGNAL ;
    PORT
      LAYER M5 ;
        RECT 159.0240 220.2360 159.0480 220.3200 ;
    END
  END r_dd[24]
  PIN r_dd[25]
    DIRECTION OUTPUT ;
    USE SIGNAL ;
    PORT
      LAYER M5 ;
        RECT 159.2640 220.2360 159.2880 220.3200 ;
    END
  END r_dd[25]
  PIN r_dd[26]
    DIRECTION OUTPUT ;
    USE SIGNAL ;
    PORT
      LAYER M5 ;
        RECT 159.5040 220.2360 159.5280 220.3200 ;
    END
  END r_dd[26]
  PIN r_dd[27]
    DIRECTION OUTPUT ;
    USE SIGNAL ;
    PORT
      LAYER M5 ;
        RECT 159.6960 220.2360 159.7200 220.3200 ;
    END
  END r_dd[27]
  PIN r_dd[28]
    DIRECTION OUTPUT ;
    USE SIGNAL ;
    PORT
      LAYER M5 ;
        RECT 159.9360 220.2360 159.9600 220.3200 ;
    END
  END r_dd[28]
  PIN r_dd[29]
    DIRECTION OUTPUT ;
    USE SIGNAL ;
    PORT
      LAYER M5 ;
        RECT 160.1760 220.2360 160.2000 220.3200 ;
    END
  END r_dd[29]
  PIN r_dd[30]
    DIRECTION OUTPUT ;
    USE SIGNAL ;
    PORT
      LAYER M5 ;
        RECT 160.4160 220.2360 160.4400 220.3200 ;
    END
  END r_dd[30]
  PIN r_dd[31]
    DIRECTION OUTPUT ;
    USE SIGNAL ;
    PORT
      LAYER M5 ;
        RECT 160.6080 220.2360 160.6320 220.3200 ;
    END
  END r_dd[31]
  PIN r_dd[32]
    DIRECTION OUTPUT ;
    USE SIGNAL ;
    PORT
      LAYER M5 ;
        RECT 160.8480 220.2360 160.8720 220.3200 ;
    END
  END r_dd[32]
  PIN r_dd[33]
    DIRECTION OUTPUT ;
    USE SIGNAL ;
    PORT
      LAYER M5 ;
        RECT 161.0880 220.2360 161.1120 220.3200 ;
    END
  END r_dd[33]
  PIN r_dd[34]
    DIRECTION OUTPUT ;
    USE SIGNAL ;
    PORT
      LAYER M5 ;
        RECT 161.3280 220.2360 161.3520 220.3200 ;
    END
  END r_dd[34]
  PIN r_dd[35]
    DIRECTION OUTPUT ;
    USE SIGNAL ;
    PORT
      LAYER M5 ;
        RECT 161.5680 220.2360 161.5920 220.3200 ;
    END
  END r_dd[35]
  PIN r_dd[36]
    DIRECTION OUTPUT ;
    USE SIGNAL ;
    PORT
      LAYER M5 ;
        RECT 161.7600 220.2360 161.7840 220.3200 ;
    END
  END r_dd[36]
  PIN r_dd[37]
    DIRECTION OUTPUT ;
    USE SIGNAL ;
    PORT
      LAYER M5 ;
        RECT 162.0000 220.2360 162.0240 220.3200 ;
    END
  END r_dd[37]
  PIN r_dd[38]
    DIRECTION OUTPUT ;
    USE SIGNAL ;
    PORT
      LAYER M5 ;
        RECT 162.2400 220.2360 162.2640 220.3200 ;
    END
  END r_dd[38]
  PIN r_dd[39]
    DIRECTION OUTPUT ;
    USE SIGNAL ;
    PORT
      LAYER M5 ;
        RECT 162.4800 220.2360 162.5040 220.3200 ;
    END
  END r_dd[39]
  PIN r_dd[40]
    DIRECTION OUTPUT ;
    USE SIGNAL ;
    PORT
      LAYER M5 ;
        RECT 162.6720 220.2360 162.6960 220.3200 ;
    END
  END r_dd[40]
  PIN r_dd[41]
    DIRECTION OUTPUT ;
    USE SIGNAL ;
    PORT
      LAYER M5 ;
        RECT 162.9120 220.2360 162.9360 220.3200 ;
    END
  END r_dd[41]
  PIN r_dd[42]
    DIRECTION OUTPUT ;
    USE SIGNAL ;
    PORT
      LAYER M5 ;
        RECT 163.1520 220.2360 163.1760 220.3200 ;
    END
  END r_dd[42]
  PIN r_dd[43]
    DIRECTION OUTPUT ;
    USE SIGNAL ;
    PORT
      LAYER M5 ;
        RECT 163.3920 220.2360 163.4160 220.3200 ;
    END
  END r_dd[43]
  PIN r_dd[44]
    DIRECTION OUTPUT ;
    USE SIGNAL ;
    PORT
      LAYER M5 ;
        RECT 163.6320 220.2360 163.6560 220.3200 ;
    END
  END r_dd[44]
  PIN r_dd[45]
    DIRECTION OUTPUT ;
    USE SIGNAL ;
    PORT
      LAYER M5 ;
        RECT 163.8240 220.2360 163.8480 220.3200 ;
    END
  END r_dd[45]
  PIN r_dd[46]
    DIRECTION OUTPUT ;
    USE SIGNAL ;
    PORT
      LAYER M5 ;
        RECT 164.0640 220.2360 164.0880 220.3200 ;
    END
  END r_dd[46]
  PIN r_dd[47]
    DIRECTION OUTPUT ;
    USE SIGNAL ;
    PORT
      LAYER M5 ;
        RECT 164.3040 220.2360 164.3280 220.3200 ;
    END
  END r_dd[47]
  PIN r_dd[48]
    DIRECTION OUTPUT ;
    USE SIGNAL ;
    PORT
      LAYER M5 ;
        RECT 164.5440 220.2360 164.5680 220.3200 ;
    END
  END r_dd[48]
  PIN r_dd[49]
    DIRECTION OUTPUT ;
    USE SIGNAL ;
    PORT
      LAYER M5 ;
        RECT 164.7360 220.2360 164.7600 220.3200 ;
    END
  END r_dd[49]
  PIN r_dd[50]
    DIRECTION OUTPUT ;
    USE SIGNAL ;
    PORT
      LAYER M5 ;
        RECT 164.9760 220.2360 165.0000 220.3200 ;
    END
  END r_dd[50]
  PIN r_dd[51]
    DIRECTION OUTPUT ;
    USE SIGNAL ;
    PORT
      LAYER M5 ;
        RECT 165.2160 220.2360 165.2400 220.3200 ;
    END
  END r_dd[51]
  PIN r_dd[52]
    DIRECTION OUTPUT ;
    USE SIGNAL ;
    PORT
      LAYER M5 ;
        RECT 165.4560 220.2360 165.4800 220.3200 ;
    END
  END r_dd[52]
  PIN r_dd[53]
    DIRECTION OUTPUT ;
    USE SIGNAL ;
    PORT
      LAYER M5 ;
        RECT 165.6960 220.2360 165.7200 220.3200 ;
    END
  END r_dd[53]
  PIN r_dd[54]
    DIRECTION OUTPUT ;
    USE SIGNAL ;
    PORT
      LAYER M5 ;
        RECT 165.8880 220.2360 165.9120 220.3200 ;
    END
  END r_dd[54]
  PIN r_dd[55]
    DIRECTION OUTPUT ;
    USE SIGNAL ;
    PORT
      LAYER M5 ;
        RECT 166.1280 220.2360 166.1520 220.3200 ;
    END
  END r_dd[55]
  PIN r_dd[56]
    DIRECTION OUTPUT ;
    USE SIGNAL ;
    PORT
      LAYER M5 ;
        RECT 166.3680 220.2360 166.3920 220.3200 ;
    END
  END r_dd[56]
  PIN r_dd[57]
    DIRECTION OUTPUT ;
    USE SIGNAL ;
    PORT
      LAYER M5 ;
        RECT 166.6080 220.2360 166.6320 220.3200 ;
    END
  END r_dd[57]
  PIN r_dd[58]
    DIRECTION OUTPUT ;
    USE SIGNAL ;
    PORT
      LAYER M5 ;
        RECT 166.8480 220.2360 166.8720 220.3200 ;
    END
  END r_dd[58]
  PIN r_dd[59]
    DIRECTION OUTPUT ;
    USE SIGNAL ;
    PORT
      LAYER M5 ;
        RECT 167.0400 220.2360 167.0640 220.3200 ;
    END
  END r_dd[59]
  PIN r_dd[60]
    DIRECTION OUTPUT ;
    USE SIGNAL ;
    PORT
      LAYER M5 ;
        RECT 167.2800 220.2360 167.3040 220.3200 ;
    END
  END r_dd[60]
  PIN r_dd[61]
    DIRECTION OUTPUT ;
    USE SIGNAL ;
    PORT
      LAYER M5 ;
        RECT 167.5200 220.2360 167.5440 220.3200 ;
    END
  END r_dd[61]
  PIN r_dd[62]
    DIRECTION OUTPUT ;
    USE SIGNAL ;
    PORT
      LAYER M5 ;
        RECT 167.7600 220.2360 167.7840 220.3200 ;
    END
  END r_dd[62]
  PIN r_dd[63]
    DIRECTION OUTPUT ;
    USE SIGNAL ;
    PORT
      LAYER M5 ;
        RECT 167.9520 220.2360 167.9760 220.3200 ;
    END
  END r_dd[63]
  PIN fault[0]
    DIRECTION OUTPUT ;
    USE SIGNAL ;
    PORT
      LAYER M5 ;
        RECT 168.1920 220.2360 168.2160 220.3200 ;
    END
  END fault[0]
  PIN fault[1]
    DIRECTION OUTPUT ;
    USE SIGNAL ;
    PORT
      LAYER M5 ;
        RECT 168.4320 220.2360 168.4560 220.3200 ;
    END
  END fault[1]
END ot_s81dv_eng_finish2
END LIBRARY
